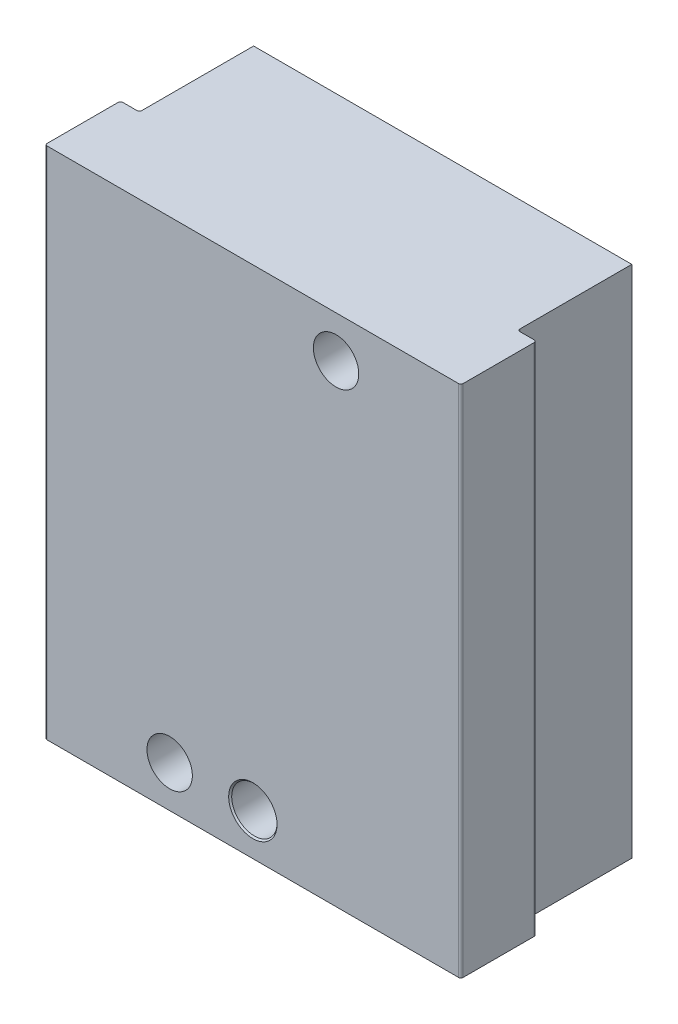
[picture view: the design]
ISO-10303-21;
HEADER;
FILE_DESCRIPTION(('STEP AP214'),'2;1');
FILE_NAME('part.step','',(''),(''),'','','');
FILE_SCHEMA(('AUTOMOTIVE_DESIGN { 1 0 10303 214 1 1 1 1 }'));
ENDSEC;
DATA;
#1=APPLICATION_CONTEXT('core data for automotive mechanical design processes');
#2=APPLICATION_PROTOCOL_DEFINITION('international standard','automotive_design',2000,#1);
#3=PRODUCT_CONTEXT('',#1,'mechanical');
#4=PRODUCT('Part','Part','',(#3));
#5=PRODUCT_RELATED_PRODUCT_CATEGORY('part','',(#4));
#6=PRODUCT_DEFINITION_FORMATION('','',#4);
#7=PRODUCT_DEFINITION_CONTEXT('part definition',#1,'design');
#8=PRODUCT_DEFINITION('design','',#6,#7);
#9=PRODUCT_DEFINITION_SHAPE('','',#8);
#10=(LENGTH_UNIT() NAMED_UNIT(*) SI_UNIT(.MILLI.,.METRE.));
#11=(NAMED_UNIT(*) PLANE_ANGLE_UNIT() SI_UNIT($,.RADIAN.));
#12=(NAMED_UNIT(*) SI_UNIT($,.STERADIAN.) SOLID_ANGLE_UNIT());
#13=UNCERTAINTY_MEASURE_WITH_UNIT(LENGTH_MEASURE(1.E-05),#10,'distance_accuracy_value','');
#14=(GEOMETRIC_REPRESENTATION_CONTEXT(3) GLOBAL_UNCERTAINTY_ASSIGNED_CONTEXT((#13)) GLOBAL_UNIT_ASSIGNED_CONTEXT((#10,
#11,#12)) REPRESENTATION_CONTEXT('',''));
#15=CARTESIAN_POINT('',(0.,0.,0.));
#16=DIRECTION('',(0.,0.,1.));
#17=DIRECTION('',(1.,0.,0.));
#18=AXIS2_PLACEMENT_3D('',#15,#16,#17);
#19=CARTESIAN_POINT('',(0.,5.5,0.));
#20=DIRECTION('',(0.,0.,-1.));
#21=DIRECTION('',(-1.,0.,0.));
#22=AXIS2_PLACEMENT_3D('',#19,#20,#21);
#23=CYLINDRICAL_SURFACE('',#22,1.5);
#24=CARTESIAN_POINT('',(0.,5.5,-25.1));
#25=DIRECTION('',(0.,0.,-1.));
#26=DIRECTION('',(-1.,0.,0.));
#27=AXIS2_PLACEMENT_3D('',#24,#25,#26);
#28=CIRCLE('',#27,1.5);
#29=CARTESIAN_POINT('',(-1.5,5.5,-25.1));
#30=VERTEX_POINT('',#29);
#31=EDGE_CURVE('E572',#30,#30,#28,.T.);
#32=ORIENTED_EDGE('',*,*,#31,.T.);
#33=EDGE_LOOP('',(#32));
#34=FACE_BOUND('',#33,.T.);
#35=CARTESIAN_POINT('',(0.,5.5,-10.));
#36=DIRECTION('',(0.,0.,1.));
#37=DIRECTION('',(1.,0.,0.));
#38=AXIS2_PLACEMENT_3D('',#35,#36,#37);
#39=CIRCLE('',#38,1.5);
#40=CARTESIAN_POINT('',(1.5,5.5,-10.));
#41=VERTEX_POINT('',#40);
#42=EDGE_CURVE('E571',#41,#41,#39,.F.);
#43=ORIENTED_EDGE('',*,*,#42,.F.);
#44=EDGE_LOOP('',(#43));
#45=FACE_BOUND('',#44,.T.);
#46=ADVANCED_FACE('F33',(#34,#45),#23,.F.);
#47=CARTESIAN_POINT('',(27.5,68.,-10.));
#48=DIRECTION('',(-1.,0.,0.));
#49=DIRECTION('',(0.,0.,1.));
#50=AXIS2_PLACEMENT_3D('',#47,#48,#49);
#51=PLANE('',#50);
#52=DIRECTION('',(0.,0.,-1.));
#53=VECTOR('',#52,1.);
#54=CARTESIAN_POINT('',(27.5,0.,-10.));
#55=LINE('',#54,#53);
#56=CARTESIAN_POINT('',(27.5,0.,-0.3));
#57=VERTEX_POINT('',#56);
#58=CARTESIAN_POINT('',(27.5,0.,-9.7));
#59=VERTEX_POINT('',#58);
#60=EDGE_CURVE('E585',#57,#59,#55,.T.);
#61=ORIENTED_EDGE('',*,*,#60,.T.);
#62=DIRECTION('',(0.,-1.,0.));
#63=VECTOR('',#62,1.);
#64=CARTESIAN_POINT('',(27.5,68.,-9.7));
#65=LINE('',#64,#63);
#66=CARTESIAN_POINT('',(27.5,68.,-9.7));
#67=VERTEX_POINT('',#66);
#68=EDGE_CURVE('E653',#59,#67,#65,.F.);
#69=ORIENTED_EDGE('',*,*,#68,.T.);
#70=DIRECTION('',(0.,0.,-1.));
#71=VECTOR('',#70,1.);
#72=CARTESIAN_POINT('',(27.5,68.,-10.));
#73=LINE('',#72,#71);
#74=CARTESIAN_POINT('',(27.5,68.,-0.3));
#75=VERTEX_POINT('',#74);
#76=EDGE_CURVE('E588',#75,#67,#73,.T.);
#77=ORIENTED_EDGE('',*,*,#76,.F.);
#78=DIRECTION('',(0.,-1.,0.));
#79=VECTOR('',#78,1.);
#80=CARTESIAN_POINT('',(27.5,68.,-0.3));
#81=LINE('',#80,#79);
#82=EDGE_CURVE('E650',#75,#57,#81,.T.);
#83=ORIENTED_EDGE('',*,*,#82,.T.);
#84=EDGE_LOOP('',(#61,#69,#77,#83));
#85=FACE_BOUND('',#84,.T.);
#86=ADVANCED_FACE('F893',(#85),#51,.F.);
#87=CARTESIAN_POINT('',(27.5,68.,-10.));
#88=DIRECTION('',(0.,0.,1.));
#89=DIRECTION('',(1.,0.,0.));
#90=AXIS2_PLACEMENT_3D('',#87,#88,#89);
#91=PLANE('',#90);
#92=DIRECTION('',(-1.,0.,0.));
#93=VECTOR('',#92,1.);
#94=CARTESIAN_POINT('',(27.5,68.,-10.));
#95=LINE('',#94,#93);
#96=CARTESIAN_POINT('',(27.2,68.,-10.));
#97=VERTEX_POINT('',#96);
#98=CARTESIAN_POINT('',(25.3,68.,-10.));
#99=VERTEX_POINT('',#98);
#100=EDGE_CURVE('E591',#97,#99,#95,.T.);
#101=ORIENTED_EDGE('',*,*,#100,.F.);
#102=DIRECTION('',(0.,-1.,0.));
#103=VECTOR('',#102,1.);
#104=CARTESIAN_POINT('',(27.2,68.,-10.));
#105=LINE('',#104,#103);
#106=CARTESIAN_POINT('',(27.2,0.,-10.));
#107=VERTEX_POINT('',#106);
#108=EDGE_CURVE('E639',#97,#107,#105,.T.);
#109=ORIENTED_EDGE('',*,*,#108,.T.);
#110=DIRECTION('',(-1.,0.,0.));
#111=VECTOR('',#110,1.);
#112=CARTESIAN_POINT('',(27.5,0.,-10.));
#113=LINE('',#112,#111);
#114=CARTESIAN_POINT('',(25.3,0.,-10.));
#115=VERTEX_POINT('',#114);
#116=EDGE_CURVE('E614',#107,#115,#113,.T.);
#117=ORIENTED_EDGE('',*,*,#116,.T.);
#118=DIRECTION('',(0.,-1.,0.));
#119=VECTOR('',#118,1.);
#120=CARTESIAN_POINT('',(25.3,68.,-10.));
#121=LINE('',#120,#119);
#122=EDGE_CURVE('E637',#115,#99,#121,.F.);
#123=ORIENTED_EDGE('',*,*,#122,.T.);
#124=EDGE_LOOP('',(#101,#109,#117,#123));
#125=FACE_BOUND('',#124,.T.);
#126=ADVANCED_FACE('F899',(#125),#91,.F.);
#127=CARTESIAN_POINT('',(25.,68.,-25.1));
#128=DIRECTION('',(-1.,0.,0.));
#129=DIRECTION('',(0.,0.,1.));
#130=AXIS2_PLACEMENT_3D('',#127,#128,#129);
#131=PLANE('',#130);
#132=DIRECTION('',(0.,0.,-1.));
#133=VECTOR('',#132,1.);
#134=CARTESIAN_POINT('',(25.,68.,-25.1));
#135=LINE('',#134,#133);
#136=CARTESIAN_POINT('',(25.,68.,-10.3));
#137=VERTEX_POINT('',#136);
#138=CARTESIAN_POINT('',(25.,68.,-25.1));
#139=VERTEX_POINT('',#138);
#140=EDGE_CURVE('E595',#137,#139,#135,.T.);
#141=ORIENTED_EDGE('',*,*,#140,.F.);
#142=DIRECTION('',(0.,-1.,0.));
#143=VECTOR('',#142,1.);
#144=CARTESIAN_POINT('',(25.,0.,-10.3));
#145=LINE('',#144,#143);
#146=CARTESIAN_POINT('',(25.,0.,-10.3));
#147=VERTEX_POINT('',#146);
#148=EDGE_CURVE('E663',#137,#147,#145,.T.);
#149=ORIENTED_EDGE('',*,*,#148,.T.);
#150=DIRECTION('',(0.,0.,-1.));
#151=VECTOR('',#150,1.);
#152=CARTESIAN_POINT('',(25.,0.,-25.1));
#153=LINE('',#152,#151);
#154=CARTESIAN_POINT('',(25.,0.,-25.1));
#155=VERTEX_POINT('',#154);
#156=EDGE_CURVE('E617',#147,#155,#153,.T.);
#157=ORIENTED_EDGE('',*,*,#156,.T.);
#158=DIRECTION('',(0.,-1.,0.));
#159=VECTOR('',#158,1.);
#160=CARTESIAN_POINT('',(25.,68.,-25.1));
#161=LINE('',#160,#159);
#162=EDGE_CURVE('E634',#139,#155,#161,.T.);
#163=ORIENTED_EDGE('',*,*,#162,.F.);
#164=EDGE_LOOP('',(#141,#149,#157,#163));
#165=FACE_BOUND('',#164,.T.);
#166=ADVANCED_FACE('F944',(#165),#131,.F.);
#167=CARTESIAN_POINT('',(-25.,68.,-25.1));
#168=DIRECTION('',(0.,0.,1.));
#169=DIRECTION('',(1.,0.,0.));
#170=AXIS2_PLACEMENT_3D('',#167,#168,#169);
#171=PLANE('',#170);
#172=DIRECTION('',(0.,1.,0.));
#173=VECTOR('',#172,1.);
#174=CARTESIAN_POINT('',(-16.125,68.,-25.1));
#175=LINE('',#174,#173);
#176=CARTESIAN_POINT('',(-16.125,14.525,-25.1));
#177=VERTEX_POINT('',#176);
#178=CARTESIAN_POINT('',(-16.125,18.9237901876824,-25.1));
#179=VERTEX_POINT('',#178);
#180=EDGE_CURVE('E41',#177,#179,#175,.T.);
#181=ORIENTED_EDGE('',*,*,#180,.F.);
#182=CARTESIAN_POINT('',(-14.075,14.525,-25.1));
#183=DIRECTION('',(0.,0.,1.));
#184=DIRECTION('',(1.,0.,0.));
#185=AXIS2_PLACEMENT_3D('',#182,#183,#184);
#186=CIRCLE('',#185,2.05);
#187=CARTESIAN_POINT('',(-14.075,12.475,-25.1));
#188=VERTEX_POINT('',#187);
#189=EDGE_CURVE('E11',#177,#188,#186,.T.);
#190=ORIENTED_EDGE('',*,*,#189,.T.);
#191=DIRECTION('',(-1.,0.,0.));
#192=VECTOR('',#191,1.);
#193=CARTESIAN_POINT('',(-25.,12.475,-25.1));
#194=LINE('',#193,#192);
#195=CARTESIAN_POINT('',(-7.92500000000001,12.475,-25.1));
#196=VERTEX_POINT('',#195);
#197=EDGE_CURVE('E787',#196,#188,#194,.T.);
#198=ORIENTED_EDGE('',*,*,#197,.F.);
#199=CARTESIAN_POINT('',(-7.92500000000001,14.525,-25.1));
#200=DIRECTION('',(0.,0.,1.));
#201=DIRECTION('',(1.,0.,0.));
#202=AXIS2_PLACEMENT_3D('',#199,#200,#201);
#203=CIRCLE('',#202,2.05);
#204=CARTESIAN_POINT('',(-5.87500000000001,14.525,-25.1));
#205=VERTEX_POINT('',#204);
#206=EDGE_CURVE('E781',#196,#205,#203,.T.);
#207=ORIENTED_EDGE('',*,*,#206,.T.);
#208=DIRECTION('',(0.,-1.,0.));
#209=VECTOR('',#208,1.);
#210=CARTESIAN_POINT('',(-5.87499999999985,67.9999999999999,-25.1));
#211=LINE('',#210,#209);
#212=CARTESIAN_POINT('',(-5.87499999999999,18.9237901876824,-25.1));
#213=VERTEX_POINT('',#212);
#214=EDGE_CURVE('E779',#213,#205,#211,.T.);
#215=ORIENTED_EDGE('',*,*,#214,.F.);
#216=CARTESIAN_POINT('',(-7.92499999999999,18.9237901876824,-25.1));
#217=DIRECTION('',(0.,0.,1.));
#218=DIRECTION('',(1.,0.,0.));
#219=AXIS2_PLACEMENT_3D('',#216,#217,#218);
#220=CIRCLE('',#219,2.05);
#221=CARTESIAN_POINT('',(-6.285,20.1537901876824,-25.1));
#222=VERTEX_POINT('',#221);
#223=EDGE_CURVE('E774',#213,#222,#220,.T.);
#224=ORIENTED_EDGE('',*,*,#223,.T.);
#225=CARTESIAN_POINT('',(0.274999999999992,25.0737901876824,-25.1));
#226=DIRECTION('',(0.,0.,1.));
#227=DIRECTION('',(1.,0.,0.));
#228=AXIS2_PLACEMENT_3D('',#225,#226,#227);
#229=CIRCLE('',#228,8.2);
#230=CARTESIAN_POINT('',(-7.92500000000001,25.0737901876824,-25.1));
#231=VERTEX_POINT('',#230);
#232=EDGE_CURVE('E769',#231,#222,#229,.T.);
#233=ORIENTED_EDGE('',*,*,#232,.F.);
#234=DIRECTION('',(0.,-1.,0.));
#235=VECTOR('',#234,1.);
#236=CARTESIAN_POINT('',(-7.92500000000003,68.,-25.1));
#237=LINE('',#236,#235);
#238=CARTESIAN_POINT('',(-7.92500000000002,42.9262098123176,-25.1));
#239=VERTEX_POINT('',#238);
#240=EDGE_CURVE('E764',#239,#231,#237,.T.);
#241=ORIENTED_EDGE('',*,*,#240,.F.);
#242=CARTESIAN_POINT('',(0.274999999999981,42.9262098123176,-25.1));
#243=DIRECTION('',(0.,0.,1.));
#244=DIRECTION('',(1.,0.,0.));
#245=AXIS2_PLACEMENT_3D('',#242,#243,#244);
#246=CIRCLE('',#245,8.2);
#247=CARTESIAN_POINT('',(-6.28500000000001,47.8462098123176,-25.1));
#248=VERTEX_POINT('',#247);
#249=EDGE_CURVE('E760',#248,#239,#246,.T.);
#250=ORIENTED_EDGE('',*,*,#249,.F.);
#251=CARTESIAN_POINT('',(-7.92500000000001,49.0762098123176,-25.1));
#252=DIRECTION('',(0.,0.,1.));
#253=DIRECTION('',(1.,0.,0.));
#254=AXIS2_PLACEMENT_3D('',#251,#252,#253);
#255=CIRCLE('',#254,2.05);
#256=CARTESIAN_POINT('',(-5.87500000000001,49.0762098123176,-25.1));
#257=VERTEX_POINT('',#256);
#258=EDGE_CURVE('E754',#248,#257,#255,.T.);
#259=ORIENTED_EDGE('',*,*,#258,.T.);
#260=DIRECTION('',(0.,-1.,0.));
#261=VECTOR('',#260,1.);
#262=CARTESIAN_POINT('',(-5.87500000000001,68.,-25.1));
#263=LINE('',#262,#261);
#264=CARTESIAN_POINT('',(-5.87500000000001,53.475,-25.1));
#265=VERTEX_POINT('',#264);
#266=EDGE_CURVE('E752',#265,#257,#263,.T.);
#267=ORIENTED_EDGE('',*,*,#266,.F.);
#268=CARTESIAN_POINT('',(-7.92500000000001,53.475,-25.1));
#269=DIRECTION('',(0.,0.,1.));
#270=DIRECTION('',(1.,0.,0.));
#271=AXIS2_PLACEMENT_3D('',#268,#269,#270);
#272=CIRCLE('',#271,2.05);
#273=CARTESIAN_POINT('',(-7.92500000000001,55.525,-25.1));
#274=VERTEX_POINT('',#273);
#275=EDGE_CURVE('E747',#265,#274,#272,.T.);
#276=ORIENTED_EDGE('',*,*,#275,.T.);
#277=DIRECTION('',(1.,0.,0.));
#278=VECTOR('',#277,1.);
#279=CARTESIAN_POINT('',(-25.,55.525,-25.1));
#280=LINE('',#279,#278);
#281=CARTESIAN_POINT('',(-14.075,55.525,-25.1));
#282=VERTEX_POINT('',#281);
#283=EDGE_CURVE('E750',#282,#274,#280,.T.);
#284=ORIENTED_EDGE('',*,*,#283,.F.);
#285=CARTESIAN_POINT('',(-14.075,53.475,-25.1));
#286=DIRECTION('',(0.,0.,1.));
#287=DIRECTION('',(1.,0.,0.));
#288=AXIS2_PLACEMENT_3D('',#285,#286,#287);
#289=CIRCLE('',#288,2.05);
#290=CARTESIAN_POINT('',(-16.125,53.475,-25.1));
#291=VERTEX_POINT('',#290);
#292=EDGE_CURVE('E757',#282,#291,#289,.T.);
#293=ORIENTED_EDGE('',*,*,#292,.T.);
#294=DIRECTION('',(0.,1.,0.));
#295=VECTOR('',#294,1.);
#296=CARTESIAN_POINT('',(-16.125,68.,-25.1));
#297=LINE('',#296,#295);
#298=CARTESIAN_POINT('',(-16.125,49.0762098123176,-25.1));
#299=VERTEX_POINT('',#298);
#300=EDGE_CURVE('E762',#299,#291,#297,.T.);
#301=ORIENTED_EDGE('',*,*,#300,.F.);
#302=CARTESIAN_POINT('',(-14.075,49.0762098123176,-25.1));
#303=DIRECTION('',(0.,0.,1.));
#304=DIRECTION('',(1.,0.,0.));
#305=AXIS2_PLACEMENT_3D('',#302,#303,#304);
#306=CIRCLE('',#305,2.05);
#307=CARTESIAN_POINT('',(-15.715,47.8462098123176,-25.1));
#308=VERTEX_POINT('',#307);
#309=EDGE_CURVE('E766',#299,#308,#306,.T.);
#310=ORIENTED_EDGE('',*,*,#309,.T.);
#311=CARTESIAN_POINT('',(-22.275,42.9262098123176,-25.1));
#312=DIRECTION('',(0.,0.,1.));
#313=DIRECTION('',(1.,0.,0.));
#314=AXIS2_PLACEMENT_3D('',#311,#312,#313);
#315=CIRCLE('',#314,8.2);
#316=CARTESIAN_POINT('',(-14.075,42.9262098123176,-25.1));
#317=VERTEX_POINT('',#316);
#318=EDGE_CURVE('E771',#317,#308,#315,.T.);
#319=ORIENTED_EDGE('',*,*,#318,.F.);
#320=DIRECTION('',(0.,1.,0.));
#321=VECTOR('',#320,1.);
#322=CARTESIAN_POINT('',(-14.075,68.,-25.1));
#323=LINE('',#322,#321);
#324=CARTESIAN_POINT('',(-14.075,25.0737901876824,-25.1));
#325=VERTEX_POINT('',#324);
#326=EDGE_CURVE('E402',#325,#317,#323,.T.);
#327=ORIENTED_EDGE('',*,*,#326,.F.);
#328=CARTESIAN_POINT('',(-22.275,25.0737901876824,-25.1));
#329=DIRECTION('',(0.,0.,1.));
#330=DIRECTION('',(1.,0.,0.));
#331=AXIS2_PLACEMENT_3D('',#328,#329,#330);
#332=CIRCLE('',#331,8.2);
#333=CARTESIAN_POINT('',(-15.715,20.1537901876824,-25.1));
#334=VERTEX_POINT('',#333);
#335=EDGE_CURVE('E777',#334,#325,#332,.T.);
#336=ORIENTED_EDGE('',*,*,#335,.F.);
#337=CARTESIAN_POINT('',(-14.075,18.9237901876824,-25.1));
#338=DIRECTION('',(0.,0.,1.));
#339=DIRECTION('',(1.,0.,0.));
#340=AXIS2_PLACEMENT_3D('',#337,#338,#339);
#341=CIRCLE('',#340,2.05);
#342=EDGE_CURVE('E784',#334,#179,#341,.T.);
#343=ORIENTED_EDGE('',*,*,#342,.T.);
#344=EDGE_LOOP('',(#181,#190,#198,#207,#215,#224,#233,#241,#250,#259,#267,#276,#284,#293,#301,
#310,#319,#327,#336,#343));
#345=FACE_BOUND('',#344,.T.);
#346=DIRECTION('',(-1.,0.,0.));
#347=VECTOR('',#346,1.);
#348=CARTESIAN_POINT('',(-25.,12.475,-25.1));
#349=LINE('',#348,#347);
#350=CARTESIAN_POINT('',(14.075,12.475,-25.1));
#351=VERTEX_POINT('',#350);
#352=CARTESIAN_POINT('',(7.92499999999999,12.475,-25.1));
#353=VERTEX_POINT('',#352);
#354=EDGE_CURVE('E740',#351,#353,#349,.T.);
#355=ORIENTED_EDGE('',*,*,#354,.F.);
#356=CARTESIAN_POINT('',(14.075,14.525,-25.1));
#357=DIRECTION('',(0.,0.,1.));
#358=DIRECTION('',(1.,0.,0.));
#359=AXIS2_PLACEMENT_3D('',#356,#357,#358);
#360=CIRCLE('',#359,2.05);
#361=CARTESIAN_POINT('',(16.125,14.525,-25.1));
#362=VERTEX_POINT('',#361);
#363=EDGE_CURVE('E744',#351,#362,#360,.T.);
#364=ORIENTED_EDGE('',*,*,#363,.T.);
#365=DIRECTION('',(0.,-1.,0.));
#366=VECTOR('',#365,1.);
#367=CARTESIAN_POINT('',(16.125,68.,-25.1));
#368=LINE('',#367,#366);
#369=CARTESIAN_POINT('',(16.125,18.9237901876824,-25.1));
#370=VERTEX_POINT('',#369);
#371=EDGE_CURVE('E742',#370,#362,#368,.T.);
#372=ORIENTED_EDGE('',*,*,#371,.F.);
#373=CARTESIAN_POINT('',(14.075,18.9237901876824,-25.1));
#374=DIRECTION('',(0.,0.,1.));
#375=DIRECTION('',(1.,0.,0.));
#376=AXIS2_PLACEMENT_3D('',#373,#374,#375);
#377=CIRCLE('',#376,2.05);
#378=CARTESIAN_POINT('',(15.715,20.1537901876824,-25.1));
#379=VERTEX_POINT('',#378);
#380=EDGE_CURVE('E737',#370,#379,#377,.T.);
#381=ORIENTED_EDGE('',*,*,#380,.T.);
#382=CARTESIAN_POINT('',(22.275,25.0737901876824,-25.1));
#383=DIRECTION('',(0.,0.,1.));
#384=DIRECTION('',(1.,0.,0.));
#385=AXIS2_PLACEMENT_3D('',#382,#383,#384);
#386=CIRCLE('',#385,8.2);
#387=CARTESIAN_POINT('',(14.075,25.0737901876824,-25.1));
#388=VERTEX_POINT('',#387);
#389=EDGE_CURVE('E730',#388,#379,#386,.T.);
#390=ORIENTED_EDGE('',*,*,#389,.F.);
#391=DIRECTION('',(0.,-1.,0.));
#392=VECTOR('',#391,1.);
#393=CARTESIAN_POINT('',(14.075,68.,-25.1));
#394=LINE('',#393,#392);
#395=CARTESIAN_POINT('',(14.075,42.9262098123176,-25.1));
#396=VERTEX_POINT('',#395);
#397=EDGE_CURVE('E725',#396,#388,#394,.T.);
#398=ORIENTED_EDGE('',*,*,#397,.F.);
#399=CARTESIAN_POINT('',(22.275,42.9262098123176,-25.1));
#400=DIRECTION('',(0.,0.,1.));
#401=DIRECTION('',(1.,0.,0.));
#402=AXIS2_PLACEMENT_3D('',#399,#400,#401);
#403=CIRCLE('',#402,8.2);
#404=CARTESIAN_POINT('',(15.715,47.8462098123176,-25.1));
#405=VERTEX_POINT('',#404);
#406=EDGE_CURVE('E723',#405,#396,#403,.T.);
#407=ORIENTED_EDGE('',*,*,#406,.F.);
#408=CARTESIAN_POINT('',(14.075,49.0762098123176,-25.1));
#409=DIRECTION('',(0.,0.,1.));
#410=DIRECTION('',(1.,0.,0.));
#411=AXIS2_PLACEMENT_3D('',#408,#409,#410);
#412=CIRCLE('',#411,2.05);
#413=CARTESIAN_POINT('',(16.125,49.0762098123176,-25.1));
#414=VERTEX_POINT('',#413);
#415=EDGE_CURVE('E718',#405,#414,#412,.T.);
#416=ORIENTED_EDGE('',*,*,#415,.T.);
#417=DIRECTION('',(0.,-1.,0.));
#418=VECTOR('',#417,1.);
#419=CARTESIAN_POINT('',(16.125,68.,-25.1));
#420=LINE('',#419,#418);
#421=CARTESIAN_POINT('',(16.125,53.475,-25.1));
#422=VERTEX_POINT('',#421);
#423=EDGE_CURVE('E714',#422,#414,#420,.T.);
#424=ORIENTED_EDGE('',*,*,#423,.F.);
#425=CARTESIAN_POINT('',(14.075,53.475,-25.1));
#426=DIRECTION('',(0.,0.,1.));
#427=DIRECTION('',(1.,0.,0.));
#428=AXIS2_PLACEMENT_3D('',#425,#426,#427);
#429=CIRCLE('',#428,2.05);
#430=CARTESIAN_POINT('',(14.075,55.525,-25.1));
#431=VERTEX_POINT('',#430);
#432=EDGE_CURVE('E709',#422,#431,#429,.T.);
#433=ORIENTED_EDGE('',*,*,#432,.T.);
#434=DIRECTION('',(1.,0.,0.));
#435=VECTOR('',#434,1.);
#436=CARTESIAN_POINT('',(-25.,55.525,-25.1));
#437=LINE('',#436,#435);
#438=CARTESIAN_POINT('',(7.92500000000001,55.525,-25.1));
#439=VERTEX_POINT('',#438);
#440=EDGE_CURVE('E702',#439,#431,#437,.T.);
#441=ORIENTED_EDGE('',*,*,#440,.F.);
#442=CARTESIAN_POINT('',(7.92500000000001,53.475,-25.1));
#443=DIRECTION('',(0.,0.,1.));
#444=DIRECTION('',(1.,0.,0.));
#445=AXIS2_PLACEMENT_3D('',#442,#443,#444);
#446=CIRCLE('',#445,2.05);
#447=CARTESIAN_POINT('',(5.87500000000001,53.475,-25.1));
#448=VERTEX_POINT('',#447);
#449=EDGE_CURVE('E699',#439,#448,#446,.T.);
#450=ORIENTED_EDGE('',*,*,#449,.T.);
#451=DIRECTION('',(0.,1.,0.));
#452=VECTOR('',#451,1.);
#453=CARTESIAN_POINT('',(5.87500000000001,68.,-25.1));
#454=LINE('',#453,#452);
#455=CARTESIAN_POINT('',(5.875,49.0762098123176,-25.1));
#456=VERTEX_POINT('',#455);
#457=EDGE_CURVE('E704',#456,#448,#454,.T.);
#458=ORIENTED_EDGE('',*,*,#457,.F.);
#459=CARTESIAN_POINT('',(7.92500000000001,49.0762098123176,-25.1));
#460=DIRECTION('',(0.,0.,1.));
#461=DIRECTION('',(1.,0.,0.));
#462=AXIS2_PLACEMENT_3D('',#459,#460,#461);
#463=CIRCLE('',#462,2.05);
#464=CARTESIAN_POINT('',(6.28500000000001,47.8462098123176,-25.1));
#465=VERTEX_POINT('',#464);
#466=EDGE_CURVE('E706',#456,#465,#463,.T.);
#467=ORIENTED_EDGE('',*,*,#466,.T.);
#468=CARTESIAN_POINT('',(-0.27499999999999,42.9262098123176,-25.1));
#469=DIRECTION('',(0.,0.,1.));
#470=DIRECTION('',(1.,0.,0.));
#471=AXIS2_PLACEMENT_3D('',#468,#469,#470);
#472=CIRCLE('',#471,8.2);
#473=CARTESIAN_POINT('',(7.92500000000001,42.9262098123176,-25.1));
#474=VERTEX_POINT('',#473);
#475=EDGE_CURVE('E712',#474,#465,#472,.T.);
#476=ORIENTED_EDGE('',*,*,#475,.F.);
#477=DIRECTION('',(0.,1.,0.));
#478=VECTOR('',#477,1.);
#479=CARTESIAN_POINT('',(7.92500000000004,68.,-25.1));
#480=LINE('',#479,#478);
#481=CARTESIAN_POINT('',(7.925,25.0737901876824,-25.1));
#482=VERTEX_POINT('',#481);
#483=EDGE_CURVE('E716',#482,#474,#480,.T.);
#484=ORIENTED_EDGE('',*,*,#483,.F.);
#485=CARTESIAN_POINT('',(-0.275000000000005,25.0737901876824,-25.1));
#486=DIRECTION('',(0.,0.,1.));
#487=DIRECTION('',(1.,0.,0.));
#488=AXIS2_PLACEMENT_3D('',#485,#486,#487);
#489=CIRCLE('',#488,8.2);
#490=CARTESIAN_POINT('',(6.28499999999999,20.1537901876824,-25.1));
#491=VERTEX_POINT('',#490);
#492=EDGE_CURVE('E721',#491,#482,#489,.T.);
#493=ORIENTED_EDGE('',*,*,#492,.F.);
#494=CARTESIAN_POINT('',(7.92499999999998,18.9237901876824,-25.1));
#495=DIRECTION('',(0.,0.,1.));
#496=DIRECTION('',(1.,0.,0.));
#497=AXIS2_PLACEMENT_3D('',#494,#495,#496);
#498=CIRCLE('',#497,2.05);
#499=CARTESIAN_POINT('',(5.87499999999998,18.9237901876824,-25.1));
#500=VERTEX_POINT('',#499);
#501=EDGE_CURVE('E727',#491,#500,#498,.T.);
#502=ORIENTED_EDGE('',*,*,#501,.T.);
#503=DIRECTION('',(0.,1.,0.));
#504=VECTOR('',#503,1.);
#505=CARTESIAN_POINT('',(5.87499999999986,68.0000000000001,-25.1));
#506=LINE('',#505,#504);
#507=CARTESIAN_POINT('',(5.87499999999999,14.525,-25.1));
#508=VERTEX_POINT('',#507);
#509=EDGE_CURVE('E732',#508,#500,#506,.T.);
#510=ORIENTED_EDGE('',*,*,#509,.F.);
#511=CARTESIAN_POINT('',(7.92499999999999,14.525,-25.1));
#512=DIRECTION('',(0.,0.,1.));
#513=DIRECTION('',(1.,0.,0.));
#514=AXIS2_PLACEMENT_3D('',#511,#512,#513);
#515=CIRCLE('',#514,2.05);
#516=EDGE_CURVE('E734',#508,#353,#515,.T.);
#517=ORIENTED_EDGE('',*,*,#516,.T.);
#518=EDGE_LOOP('',(#355,#364,#372,#381,#390,#398,#407,#416,#424,#433,#441,#450,#458,#467,#476,
#484,#493,#502,#510,#517));
#519=FACE_BOUND('',#518,.T.);
#520=ORIENTED_EDGE('',*,*,#31,.F.);
#521=EDGE_LOOP('',(#520));
#522=FACE_BOUND('',#521,.T.);
#523=CARTESIAN_POINT('',(-11.,5.5,-25.1));
#524=DIRECTION('',(0.,0.,-1.));
#525=DIRECTION('',(-1.,0.,0.));
#526=AXIS2_PLACEMENT_3D('',#523,#524,#525);
#527=CIRCLE('',#526,3.);
#528=CARTESIAN_POINT('',(-14.,5.5,-25.1));
#529=VERTEX_POINT('',#528);
#530=EDGE_CURVE('E575',#529,#529,#527,.T.);
#531=ORIENTED_EDGE('',*,*,#530,.F.);
#532=EDGE_LOOP('',(#531));
#533=FACE_BOUND('',#532,.T.);
#534=CARTESIAN_POINT('',(11.,62.5,-25.1));
#535=DIRECTION('',(0.,0.,-1.));
#536=DIRECTION('',(-1.,0.,0.));
#537=AXIS2_PLACEMENT_3D('',#534,#535,#536);
#538=CIRCLE('',#537,3.);
#539=CARTESIAN_POINT('',(8.,62.5,-25.1));
#540=VERTEX_POINT('',#539);
#541=EDGE_CURVE('E579',#540,#540,#538,.T.);
#542=ORIENTED_EDGE('',*,*,#541,.F.);
#543=EDGE_LOOP('',(#542));
#544=FACE_BOUND('',#543,.T.);
#545=DIRECTION('',(-1.,0.,0.));
#546=VECTOR('',#545,1.);
#547=CARTESIAN_POINT('',(-25.,0.,-25.1));
#548=LINE('',#547,#546);
#549=CARTESIAN_POINT('',(-25.,0.,-25.1));
#550=VERTEX_POINT('',#549);
#551=EDGE_CURVE('E619',#155,#550,#548,.T.);
#552=ORIENTED_EDGE('',*,*,#551,.T.);
#553=DIRECTION('',(0.,-1.,0.));
#554=VECTOR('',#553,1.);
#555=CARTESIAN_POINT('',(-25.,68.,-25.1));
#556=LINE('',#555,#554);
#557=CARTESIAN_POINT('',(-25.,68.,-25.1));
#558=VERTEX_POINT('',#557);
#559=EDGE_CURVE('E611',#558,#550,#556,.T.);
#560=ORIENTED_EDGE('',*,*,#559,.F.);
#561=DIRECTION('',(-1.,0.,0.));
#562=VECTOR('',#561,1.);
#563=CARTESIAN_POINT('',(-25.,68.,-25.1));
#564=LINE('',#563,#562);
#565=EDGE_CURVE('E597',#139,#558,#564,.T.);
#566=ORIENTED_EDGE('',*,*,#565,.F.);
#567=ORIENTED_EDGE('',*,*,#162,.T.);
#568=EDGE_LOOP('',(#552,#560,#566,#567));
#569=FACE_BOUND('',#568,.T.);
#570=ADVANCED_FACE('F800',(#345,#519,#522,#533,#544,#569),#171,.F.);
#571=CARTESIAN_POINT('',(-25.,68.,-25.1));
#572=DIRECTION('',(1.,0.,0.));
#573=DIRECTION('',(0.,0.,-1.));
#574=AXIS2_PLACEMENT_3D('',#571,#572,#573);
#575=PLANE('',#574);
#576=DIRECTION('',(0.,0.,1.));
#577=VECTOR('',#576,1.);
#578=CARTESIAN_POINT('',(-25.,0.,-25.1));
#579=LINE('',#578,#577);
#580=CARTESIAN_POINT('',(-25.,0.,-10.3));
#581=VERTEX_POINT('',#580);
#582=EDGE_CURVE('E621',#550,#581,#579,.T.);
#583=ORIENTED_EDGE('',*,*,#582,.T.);
#584=DIRECTION('',(0.,-1.,0.));
#585=VECTOR('',#584,1.);
#586=CARTESIAN_POINT('',(-25.,68.,-10.3));
#587=LINE('',#586,#585);
#588=CARTESIAN_POINT('',(-25.,68.,-10.3));
#589=VERTEX_POINT('',#588);
#590=EDGE_CURVE('E671',#581,#589,#587,.F.);
#591=ORIENTED_EDGE('',*,*,#590,.T.);
#592=DIRECTION('',(0.,0.,1.));
#593=VECTOR('',#592,1.);
#594=CARTESIAN_POINT('',(-25.,68.,-25.1));
#595=LINE('',#594,#593);
#596=EDGE_CURVE('E599',#558,#589,#595,.T.);
#597=ORIENTED_EDGE('',*,*,#596,.F.);
#598=ORIENTED_EDGE('',*,*,#559,.T.);
#599=EDGE_LOOP('',(#583,#591,#597,#598));
#600=FACE_BOUND('',#599,.T.);
#601=ADVANCED_FACE('F937',(#600),#575,.F.);
#602=CARTESIAN_POINT('',(-27.5,68.,-10.));
#603=DIRECTION('',(0.,0.,1.));
#604=DIRECTION('',(1.,0.,0.));
#605=AXIS2_PLACEMENT_3D('',#602,#603,#604);
#606=PLANE('',#605);
#607=DIRECTION('',(-1.,0.,0.));
#608=VECTOR('',#607,1.);
#609=CARTESIAN_POINT('',(-27.5,68.,-10.));
#610=LINE('',#609,#608);
#611=CARTESIAN_POINT('',(-25.3,68.,-10.));
#612=VERTEX_POINT('',#611);
#613=CARTESIAN_POINT('',(-27.2,68.,-10.));
#614=VERTEX_POINT('',#613);
#615=EDGE_CURVE('E602',#612,#614,#610,.T.);
#616=ORIENTED_EDGE('',*,*,#615,.F.);
#617=DIRECTION('',(0.,-1.,0.));
#618=VECTOR('',#617,1.);
#619=CARTESIAN_POINT('',(-25.3,0.,-10.));
#620=LINE('',#619,#618);
#621=CARTESIAN_POINT('',(-25.3,0.,-10.));
#622=VERTEX_POINT('',#621);
#623=EDGE_CURVE('E668',#612,#622,#620,.T.);
#624=ORIENTED_EDGE('',*,*,#623,.T.);
#625=DIRECTION('',(-1.,0.,0.));
#626=VECTOR('',#625,1.);
#627=CARTESIAN_POINT('',(-27.5,0.,-10.));
#628=LINE('',#627,#626);
#629=CARTESIAN_POINT('',(-27.2,0.,-10.));
#630=VERTEX_POINT('',#629);
#631=EDGE_CURVE('E624',#622,#630,#628,.T.);
#632=ORIENTED_EDGE('',*,*,#631,.T.);
#633=DIRECTION('',(0.,-1.,0.));
#634=VECTOR('',#633,1.);
#635=CARTESIAN_POINT('',(-27.2,68.,-10.));
#636=LINE('',#635,#634);
#637=EDGE_CURVE('E666',#630,#614,#636,.F.);
#638=ORIENTED_EDGE('',*,*,#637,.T.);
#639=EDGE_LOOP('',(#616,#624,#632,#638));
#640=FACE_BOUND('',#639,.T.);
#641=ADVANCED_FACE('F933',(#640),#606,.F.);
#642=CARTESIAN_POINT('',(-27.5,68.,-10.));
#643=DIRECTION('',(1.,0.,0.));
#644=DIRECTION('',(0.,0.,-1.));
#645=AXIS2_PLACEMENT_3D('',#642,#643,#644);
#646=PLANE('',#645);
#647=DIRECTION('',(0.,0.,1.));
#648=VECTOR('',#647,1.);
#649=CARTESIAN_POINT('',(-27.5,68.,-10.));
#650=LINE('',#649,#648);
#651=CARTESIAN_POINT('',(-27.5,68.,-9.7));
#652=VERTEX_POINT('',#651);
#653=CARTESIAN_POINT('',(-27.5,68.,-0.3));
#654=VERTEX_POINT('',#653);
#655=EDGE_CURVE('E605',#652,#654,#650,.T.);
#656=ORIENTED_EDGE('',*,*,#655,.F.);
#657=DIRECTION('',(0.,-1.,0.));
#658=VECTOR('',#657,1.);
#659=CARTESIAN_POINT('',(-27.5,68.,-9.7));
#660=LINE('',#659,#658);
#661=CARTESIAN_POINT('',(-27.5,0.,-9.7));
#662=VERTEX_POINT('',#661);
#663=EDGE_CURVE('E675',#652,#662,#660,.T.);
#664=ORIENTED_EDGE('',*,*,#663,.T.);
#665=DIRECTION('',(0.,0.,1.));
#666=VECTOR('',#665,1.);
#667=CARTESIAN_POINT('',(-27.5,0.,-10.));
#668=LINE('',#667,#666);
#669=CARTESIAN_POINT('',(-27.5,0.,-0.3));
#670=VERTEX_POINT('',#669);
#671=EDGE_CURVE('E627',#662,#670,#668,.T.);
#672=ORIENTED_EDGE('',*,*,#671,.T.);
#673=DIRECTION('',(0.,-1.,0.));
#674=VECTOR('',#673,1.);
#675=CARTESIAN_POINT('',(-27.5,68.,-0.3));
#676=LINE('',#675,#674);
#677=EDGE_CURVE('E673',#670,#654,#676,.F.);
#678=ORIENTED_EDGE('',*,*,#677,.T.);
#679=EDGE_LOOP('',(#656,#664,#672,#678));
#680=FACE_BOUND('',#679,.T.);
#681=ADVANCED_FACE('F929',(#680),#646,.F.);
#682=CARTESIAN_POINT('',(-27.5,68.,0.));
#683=DIRECTION('',(0.,0.,-1.));
#684=DIRECTION('',(-1.,0.,0.));
#685=AXIS2_PLACEMENT_3D('',#682,#683,#684);
#686=PLANE('',#685);
#687=CARTESIAN_POINT('',(0.,5.5,0.));
#688=DIRECTION('',(0.,0.,-1.));
#689=DIRECTION('',(-1.,0.,0.));
#690=AXIS2_PLACEMENT_3D('',#687,#688,#689);
#691=CIRCLE('',#690,3.19999999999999);
#692=CARTESIAN_POINT('',(-3.19999999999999,5.5,0.));
#693=VERTEX_POINT('',#692);
#694=EDGE_CURVE('E696',#693,#693,#691,.T.);
#695=ORIENTED_EDGE('',*,*,#694,.T.);
#696=EDGE_LOOP('',(#695));
#697=FACE_BOUND('',#696,.T.);
#698=CARTESIAN_POINT('',(-11.,5.5,0.));
#699=DIRECTION('',(0.,0.,-1.));
#700=DIRECTION('',(-1.,0.,0.));
#701=AXIS2_PLACEMENT_3D('',#698,#699,#700);
#702=CIRCLE('',#701,3.);
#703=CARTESIAN_POINT('',(-14.,5.5,0.));
#704=VERTEX_POINT('',#703);
#705=EDGE_CURVE('E576',#704,#704,#702,.T.);
#706=ORIENTED_EDGE('',*,*,#705,.T.);
#707=EDGE_LOOP('',(#706));
#708=FACE_BOUND('',#707,.T.);
#709=CARTESIAN_POINT('',(11.,62.5,0.));
#710=DIRECTION('',(0.,0.,-1.));
#711=DIRECTION('',(-1.,0.,0.));
#712=AXIS2_PLACEMENT_3D('',#709,#710,#711);
#713=CIRCLE('',#712,3.);
#714=CARTESIAN_POINT('',(8.,62.5,0.));
#715=VERTEX_POINT('',#714);
#716=EDGE_CURVE('E582',#715,#715,#713,.T.);
#717=ORIENTED_EDGE('',*,*,#716,.T.);
#718=EDGE_LOOP('',(#717));
#719=FACE_BOUND('',#718,.T.);
#720=DIRECTION('',(1.,0.,0.));
#721=VECTOR('',#720,1.);
#722=CARTESIAN_POINT('',(-27.5,0.,0.));
#723=LINE('',#722,#721);
#724=CARTESIAN_POINT('',(-27.2,0.,0.));
#725=VERTEX_POINT('',#724);
#726=CARTESIAN_POINT('',(27.2,0.,0.));
#727=VERTEX_POINT('',#726);
#728=EDGE_CURVE('E592',#725,#727,#723,.T.);
#729=ORIENTED_EDGE('',*,*,#728,.T.);
#730=DIRECTION('',(0.,-1.,0.));
#731=VECTOR('',#730,1.);
#732=CARTESIAN_POINT('',(27.2,68.,0.));
#733=LINE('',#732,#731);
#734=CARTESIAN_POINT('',(27.2,68.,0.));
#735=VERTEX_POINT('',#734);
#736=EDGE_CURVE('E681',#727,#735,#733,.F.);
#737=ORIENTED_EDGE('',*,*,#736,.T.);
#738=DIRECTION('',(1.,0.,0.));
#739=VECTOR('',#738,1.);
#740=CARTESIAN_POINT('',(-27.5,68.,0.));
#741=LINE('',#740,#739);
#742=CARTESIAN_POINT('',(-27.2,68.,0.));
#743=VERTEX_POINT('',#742);
#744=EDGE_CURVE('E608',#743,#735,#741,.T.);
#745=ORIENTED_EDGE('',*,*,#744,.F.);
#746=DIRECTION('',(0.,-1.,0.));
#747=VECTOR('',#746,1.);
#748=CARTESIAN_POINT('',(-27.2,68.,0.));
#749=LINE('',#748,#747);
#750=EDGE_CURVE('E678',#743,#725,#749,.T.);
#751=ORIENTED_EDGE('',*,*,#750,.T.);
#752=EDGE_LOOP('',(#729,#737,#745,#751));
#753=FACE_BOUND('',#752,.T.);
#754=ADVANCED_FACE('F921',(#697,#708,#719,#753),#686,.F.);
#755=CARTESIAN_POINT('',(0.,68.,0.));
#756=DIRECTION('',(0.,1.,0.));
#757=DIRECTION('',(0.,0.,1.));
#758=AXIS2_PLACEMENT_3D('',#755,#756,#757);
#759=PLANE('',#758);
#760=ORIENTED_EDGE('',*,*,#76,.T.);
#761=CARTESIAN_POINT('',(27.2,68.,-9.7));
#762=DIRECTION('',(0.,1.,0.));
#763=DIRECTION('',(0.,0.,1.));
#764=AXIS2_PLACEMENT_3D('',#761,#762,#763);
#765=CIRCLE('',#764,0.3);
#766=EDGE_CURVE('E661',#67,#97,#765,.T.);
#767=ORIENTED_EDGE('',*,*,#766,.T.);
#768=ORIENTED_EDGE('',*,*,#100,.T.);
#769=CARTESIAN_POINT('',(25.3,68.,-10.3));
#770=DIRECTION('',(0.,1.,0.));
#771=DIRECTION('',(0.,0.,1.));
#772=AXIS2_PLACEMENT_3D('',#769,#770,#771);
#773=CIRCLE('',#772,0.3);
#774=EDGE_CURVE('E685',#99,#137,#773,.F.);
#775=ORIENTED_EDGE('',*,*,#774,.T.);
#776=ORIENTED_EDGE('',*,*,#140,.T.);
#777=ORIENTED_EDGE('',*,*,#565,.T.);
#778=ORIENTED_EDGE('',*,*,#596,.T.);
#779=CARTESIAN_POINT('',(-25.3,68.,-10.3));
#780=DIRECTION('',(0.,1.,0.));
#781=DIRECTION('',(0.,0.,1.));
#782=AXIS2_PLACEMENT_3D('',#779,#780,#781);
#783=CIRCLE('',#782,0.3);
#784=EDGE_CURVE('E689',#589,#612,#783,.F.);
#785=ORIENTED_EDGE('',*,*,#784,.T.);
#786=ORIENTED_EDGE('',*,*,#615,.T.);
#787=CARTESIAN_POINT('',(-27.2,68.,-9.7));
#788=DIRECTION('',(0.,1.,0.));
#789=DIRECTION('',(0.,0.,1.));
#790=AXIS2_PLACEMENT_3D('',#787,#788,#789);
#791=CIRCLE('',#790,0.3);
#792=EDGE_CURVE('E659',#614,#652,#791,.T.);
#793=ORIENTED_EDGE('',*,*,#792,.T.);
#794=ORIENTED_EDGE('',*,*,#655,.T.);
#795=CARTESIAN_POINT('',(-27.2,68.,-0.3));
#796=DIRECTION('',(0.,1.,0.));
#797=DIRECTION('',(0.,0.,1.));
#798=AXIS2_PLACEMENT_3D('',#795,#796,#797);
#799=CIRCLE('',#798,0.3);
#800=EDGE_CURVE('E655',#654,#743,#799,.T.);
#801=ORIENTED_EDGE('',*,*,#800,.T.);
#802=ORIENTED_EDGE('',*,*,#744,.T.);
#803=CARTESIAN_POINT('',(27.2,68.,-0.3));
#804=DIRECTION('',(0.,1.,0.));
#805=DIRECTION('',(0.,0.,1.));
#806=AXIS2_PLACEMENT_3D('',#803,#804,#805);
#807=CIRCLE('',#806,0.3);
#808=EDGE_CURVE('E657',#735,#75,#807,.T.);
#809=ORIENTED_EDGE('',*,*,#808,.T.);
#810=EDGE_LOOP('',(#760,#767,#768,#775,#776,#777,#778,#785,#786,#793,#794,#801,#802,#809));
#811=FACE_BOUND('',#810,.T.);
#812=ADVANCED_FACE('F917',(#811),#759,.T.);
#813=CARTESIAN_POINT('',(0.,0.,0.));
#814=DIRECTION('',(0.,1.,0.));
#815=DIRECTION('',(0.,0.,1.));
#816=AXIS2_PLACEMENT_3D('',#813,#814,#815);
#817=PLANE('',#816);
#818=ORIENTED_EDGE('',*,*,#116,.F.);
#819=CARTESIAN_POINT('',(27.2,0.,-9.7));
#820=DIRECTION('',(0.,1.,0.));
#821=DIRECTION('',(0.,0.,1.));
#822=AXIS2_PLACEMENT_3D('',#819,#820,#821);
#823=CIRCLE('',#822,0.3);
#824=EDGE_CURVE('E648',#107,#59,#823,.F.);
#825=ORIENTED_EDGE('',*,*,#824,.T.);
#826=ORIENTED_EDGE('',*,*,#60,.F.);
#827=CARTESIAN_POINT('',(27.2,0.,-0.3));
#828=DIRECTION('',(0.,1.,0.));
#829=DIRECTION('',(0.,0.,1.));
#830=AXIS2_PLACEMENT_3D('',#827,#828,#829);
#831=CIRCLE('',#830,0.3);
#832=EDGE_CURVE('E644',#57,#727,#831,.F.);
#833=ORIENTED_EDGE('',*,*,#832,.T.);
#834=ORIENTED_EDGE('',*,*,#728,.F.);
#835=CARTESIAN_POINT('',(-27.2,0.,-0.3));
#836=DIRECTION('',(0.,1.,0.));
#837=DIRECTION('',(0.,0.,1.));
#838=AXIS2_PLACEMENT_3D('',#835,#836,#837);
#839=CIRCLE('',#838,0.3);
#840=EDGE_CURVE('E642',#725,#670,#839,.F.);
#841=ORIENTED_EDGE('',*,*,#840,.T.);
#842=ORIENTED_EDGE('',*,*,#671,.F.);
#843=CARTESIAN_POINT('',(-27.2,0.,-9.7));
#844=DIRECTION('',(0.,1.,0.));
#845=DIRECTION('',(0.,0.,1.));
#846=AXIS2_PLACEMENT_3D('',#843,#844,#845);
#847=CIRCLE('',#846,0.3);
#848=EDGE_CURVE('E646',#662,#630,#847,.F.);
#849=ORIENTED_EDGE('',*,*,#848,.T.);
#850=ORIENTED_EDGE('',*,*,#631,.F.);
#851=CARTESIAN_POINT('',(-25.3,0.,-10.3));
#852=DIRECTION('',(0.,1.,0.));
#853=DIRECTION('',(0.,0.,1.));
#854=AXIS2_PLACEMENT_3D('',#851,#852,#853);
#855=CIRCLE('',#854,0.3);
#856=EDGE_CURVE('E687',#622,#581,#855,.T.);
#857=ORIENTED_EDGE('',*,*,#856,.T.);
#858=ORIENTED_EDGE('',*,*,#582,.F.);
#859=ORIENTED_EDGE('',*,*,#551,.F.);
#860=ORIENTED_EDGE('',*,*,#156,.F.);
#861=CARTESIAN_POINT('',(25.3,0.,-10.3));
#862=DIRECTION('',(0.,1.,0.));
#863=DIRECTION('',(0.,0.,1.));
#864=AXIS2_PLACEMENT_3D('',#861,#862,#863);
#865=CIRCLE('',#864,0.3);
#866=EDGE_CURVE('E683',#147,#115,#865,.T.);
#867=ORIENTED_EDGE('',*,*,#866,.T.);
#868=EDGE_LOOP('',(#818,#825,#826,#833,#834,#841,#842,#849,#850,#857,#858,#859,#860,#867));
#869=FACE_BOUND('',#868,.T.);
#870=ADVANCED_FACE('F920',(#869),#817,.F.);
#871=CARTESIAN_POINT('',(27.2,68.,-9.7));
#872=DIRECTION('',(0.,-1.,0.));
#873=DIRECTION('',(0.,0.,-1.));
#874=AXIS2_PLACEMENT_3D('',#871,#872,#873);
#875=CYLINDRICAL_SURFACE('',#874,0.3);
#876=ORIENTED_EDGE('',*,*,#766,.F.);
#877=ORIENTED_EDGE('',*,*,#68,.F.);
#878=ORIENTED_EDGE('',*,*,#824,.F.);
#879=ORIENTED_EDGE('',*,*,#108,.F.);
#880=EDGE_LOOP('',(#876,#877,#878,#879));
#881=FACE_BOUND('',#880,.T.);
#882=ADVANCED_FACE('F925',(#881),#875,.T.);
#883=CARTESIAN_POINT('',(25.3,68.,-10.3));
#884=DIRECTION('',(0.,1.,0.));
#885=DIRECTION('',(0.,0.,1.));
#886=AXIS2_PLACEMENT_3D('',#883,#884,#885);
#887=CYLINDRICAL_SURFACE('',#886,0.3);
#888=ORIENTED_EDGE('',*,*,#774,.F.);
#889=ORIENTED_EDGE('',*,*,#122,.F.);
#890=ORIENTED_EDGE('',*,*,#866,.F.);
#891=ORIENTED_EDGE('',*,*,#148,.F.);
#892=EDGE_LOOP('',(#888,#889,#890,#891));
#893=FACE_BOUND('',#892,.T.);
#894=ADVANCED_FACE('F953',(#893),#887,.F.);
#895=CARTESIAN_POINT('',(-25.3,68.,-10.3));
#896=DIRECTION('',(0.,1.,0.));
#897=DIRECTION('',(0.,0.,1.));
#898=AXIS2_PLACEMENT_3D('',#895,#896,#897);
#899=CYLINDRICAL_SURFACE('',#898,0.3);
#900=ORIENTED_EDGE('',*,*,#784,.F.);
#901=ORIENTED_EDGE('',*,*,#590,.F.);
#902=ORIENTED_EDGE('',*,*,#856,.F.);
#903=ORIENTED_EDGE('',*,*,#623,.F.);
#904=EDGE_LOOP('',(#900,#901,#902,#903));
#905=FACE_BOUND('',#904,.T.);
#906=ADVANCED_FACE('F957',(#905),#899,.F.);
#907=CARTESIAN_POINT('',(-27.2,68.,-9.7));
#908=DIRECTION('',(0.,-1.,0.));
#909=DIRECTION('',(0.,0.,-1.));
#910=AXIS2_PLACEMENT_3D('',#907,#908,#909);
#911=CYLINDRICAL_SURFACE('',#910,0.3);
#912=ORIENTED_EDGE('',*,*,#792,.F.);
#913=ORIENTED_EDGE('',*,*,#637,.F.);
#914=ORIENTED_EDGE('',*,*,#848,.F.);
#915=ORIENTED_EDGE('',*,*,#663,.F.);
#916=EDGE_LOOP('',(#912,#913,#914,#915));
#917=FACE_BOUND('',#916,.T.);
#918=ADVANCED_FACE('F961',(#917),#911,.T.);
#919=CARTESIAN_POINT('',(27.2,68.,-0.3));
#920=DIRECTION('',(0.,-1.,0.));
#921=DIRECTION('',(0.,0.,-1.));
#922=AXIS2_PLACEMENT_3D('',#919,#920,#921);
#923=CYLINDRICAL_SURFACE('',#922,0.3);
#924=ORIENTED_EDGE('',*,*,#808,.F.);
#925=ORIENTED_EDGE('',*,*,#736,.F.);
#926=ORIENTED_EDGE('',*,*,#832,.F.);
#927=ORIENTED_EDGE('',*,*,#82,.F.);
#928=EDGE_LOOP('',(#924,#925,#926,#927));
#929=FACE_BOUND('',#928,.T.);
#930=ADVANCED_FACE('F965',(#929),#923,.T.);
#931=CARTESIAN_POINT('',(-27.2,68.,-0.3));
#932=DIRECTION('',(0.,-1.,0.));
#933=DIRECTION('',(0.,0.,-1.));
#934=AXIS2_PLACEMENT_3D('',#931,#932,#933);
#935=CYLINDRICAL_SURFACE('',#934,0.3);
#936=ORIENTED_EDGE('',*,*,#800,.F.);
#937=ORIENTED_EDGE('',*,*,#677,.F.);
#938=ORIENTED_EDGE('',*,*,#840,.F.);
#939=ORIENTED_EDGE('',*,*,#750,.F.);
#940=EDGE_LOOP('',(#936,#937,#938,#939));
#941=FACE_BOUND('',#940,.T.);
#942=ADVANCED_FACE('F915',(#941),#935,.T.);
#943=CARTESIAN_POINT('',(11.,62.5,0.));
#944=DIRECTION('',(0.,0.,-1.));
#945=DIRECTION('',(-1.,0.,0.));
#946=AXIS2_PLACEMENT_3D('',#943,#944,#945);
#947=CYLINDRICAL_SURFACE('',#946,3.);
#948=ORIENTED_EDGE('',*,*,#716,.F.);
#949=EDGE_LOOP('',(#948));
#950=FACE_BOUND('',#949,.T.);
#951=ORIENTED_EDGE('',*,*,#541,.T.);
#952=EDGE_LOOP('',(#951));
#953=FACE_BOUND('',#952,.T.);
#954=ADVANCED_FACE('F911',(#950,#953),#947,.F.);
#955=CARTESIAN_POINT('',(-11.,5.5,0.));
#956=DIRECTION('',(0.,0.,-1.));
#957=DIRECTION('',(-1.,0.,0.));
#958=AXIS2_PLACEMENT_3D('',#955,#956,#957);
#959=CYLINDRICAL_SURFACE('',#958,3.);
#960=ORIENTED_EDGE('',*,*,#705,.F.);
#961=EDGE_LOOP('',(#960));
#962=FACE_BOUND('',#961,.T.);
#963=ORIENTED_EDGE('',*,*,#530,.T.);
#964=EDGE_LOOP('',(#963));
#965=FACE_BOUND('',#964,.T.);
#966=ADVANCED_FACE('F907',(#962,#965),#959,.F.);
#967=CARTESIAN_POINT('',(0.,5.5,-10.));
#968=DIRECTION('',(0.,0.,1.));
#969=DIRECTION('',(1.,0.,0.));
#970=AXIS2_PLACEMENT_3D('',#967,#968,#969);
#971=PLANE('',#970);
#972=CARTESIAN_POINT('',(0.,5.5,-10.));
#973=DIRECTION('',(0.,0.,1.));
#974=DIRECTION('',(1.,0.,0.));
#975=AXIS2_PLACEMENT_3D('',#972,#973,#974);
#976=CIRCLE('',#975,3.);
#977=CARTESIAN_POINT('',(3.,5.5,-10.));
#978=VERTEX_POINT('',#977);
#979=EDGE_CURVE('E568',#978,#978,#976,.T.);
#980=ORIENTED_EDGE('',*,*,#979,.T.);
#981=EDGE_LOOP('',(#980));
#982=FACE_BOUND('',#981,.T.);
#983=ORIENTED_EDGE('',*,*,#42,.T.);
#984=EDGE_LOOP('',(#983));
#985=FACE_BOUND('',#984,.T.);
#986=ADVANCED_FACE('F910',(#982,#985),#971,.T.);
#987=CARTESIAN_POINT('',(0.,5.5,-10.));
#988=DIRECTION('',(0.,0.,1.));
#989=DIRECTION('',(1.,0.,0.));
#990=AXIS2_PLACEMENT_3D('',#987,#988,#989);
#991=CYLINDRICAL_SURFACE('',#990,3.);
#992=CARTESIAN_POINT('',(0.,5.5,-0.200000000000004));
#993=DIRECTION('',(0.,0.,-1.));
#994=DIRECTION('',(-1.,0.,0.));
#995=AXIS2_PLACEMENT_3D('',#992,#993,#994);
#996=CIRCLE('',#995,3.);
#997=CARTESIAN_POINT('',(-3.,5.5,-0.200000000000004));
#998=VERTEX_POINT('',#997);
#999=EDGE_CURVE('E691',#998,#998,#996,.F.);
#1000=ORIENTED_EDGE('',*,*,#999,.T.);
#1001=EDGE_LOOP('',(#1000));
#1002=FACE_BOUND('',#1001,.T.);
#1003=ORIENTED_EDGE('',*,*,#979,.F.);
#1004=EDGE_LOOP('',(#1003));
#1005=FACE_BOUND('',#1004,.T.);
#1006=ADVANCED_FACE('F905',(#1002,#1005),#991,.F.);
#1007=CARTESIAN_POINT('',(0.,5.5,-0.200000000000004));
#1008=DIRECTION('',(0.,0.,1.));
#1009=DIRECTION('',(1.,0.,0.));
#1010=AXIS2_PLACEMENT_3D('',#1007,#1008,#1009);
#1011=CONICAL_SURFACE('',#1010,3.,0.785398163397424);
#1012=ORIENTED_EDGE('',*,*,#694,.F.);
#1013=EDGE_LOOP('',(#1012));
#1014=FACE_BOUND('',#1013,.T.);
#1015=ORIENTED_EDGE('',*,*,#999,.F.);
#1016=EDGE_LOOP('',(#1015));
#1017=FACE_BOUND('',#1016,.T.);
#1018=ADVANCED_FACE('F35',(#1014,#1017),#1011,.F.);
#1019=CARTESIAN_POINT('',(14.075,48.35,-25.11875));
#1020=DIRECTION('',(-1.,0.,0.));
#1021=DIRECTION('',(0.,1.,0.));
#1022=AXIS2_PLACEMENT_3D('',#1019,#1020,#1021);
#1023=PLANE('',#1022);
#1024=ORIENTED_EDGE('',*,*,#397,.T.);
#1025=DIRECTION('',(0.,0.,-1.));
#1026=VECTOR('',#1025,1.);
#1027=CARTESIAN_POINT('',(14.075,25.0737901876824,-25.11875));
#1028=LINE('',#1027,#1026);
#1029=CARTESIAN_POINT('',(14.075,25.0737901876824,-23.58125));
#1030=VERTEX_POINT('',#1029);
#1031=EDGE_CURVE('E494',#1030,#388,#1028,.T.);
#1032=ORIENTED_EDGE('',*,*,#1031,.F.);
#1033=DIRECTION('',(0.,-1.,0.));
#1034=VECTOR('',#1033,1.);
#1035=CARTESIAN_POINT('',(14.075,48.35,-23.58125));
#1036=LINE('',#1035,#1034);
#1037=CARTESIAN_POINT('',(14.075,42.9262098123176,-23.58125));
#1038=VERTEX_POINT('',#1037);
#1039=EDGE_CURVE('E470',#1038,#1030,#1036,.T.);
#1040=ORIENTED_EDGE('',*,*,#1039,.F.);
#1041=DIRECTION('',(0.,0.,1.));
#1042=VECTOR('',#1041,1.);
#1043=CARTESIAN_POINT('',(14.075,42.9262098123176,-25.11875));
#1044=LINE('',#1043,#1042);
#1045=EDGE_CURVE('E497',#396,#1038,#1044,.T.);
#1046=ORIENTED_EDGE('',*,*,#1045,.F.);
#1047=EDGE_LOOP('',(#1024,#1032,#1040,#1046));
#1048=FACE_BOUND('',#1047,.T.);
#1049=ADVANCED_FACE('F1040',(#1048),#1023,.T.);
#1050=CARTESIAN_POINT('',(16.125,19.65,-25.11875));
#1051=DIRECTION('',(-1.,0.,0.));
#1052=DIRECTION('',(0.,1.,0.));
#1053=AXIS2_PLACEMENT_3D('',#1050,#1051,#1052);
#1054=PLANE('',#1053);
#1055=ORIENTED_EDGE('',*,*,#371,.T.);
#1056=DIRECTION('',(0.,0.,1.));
#1057=VECTOR('',#1056,1.);
#1058=CARTESIAN_POINT('',(16.125,14.525,-25.11875));
#1059=LINE('',#1058,#1057);
#1060=CARTESIAN_POINT('',(16.125,14.525,-23.58125));
#1061=VERTEX_POINT('',#1060);
#1062=EDGE_CURVE('E542',#1061,#362,#1059,.F.);
#1063=ORIENTED_EDGE('',*,*,#1062,.F.);
#1064=DIRECTION('',(0.,-1.,0.));
#1065=VECTOR('',#1064,1.);
#1066=CARTESIAN_POINT('',(16.125,19.65,-23.58125));
#1067=LINE('',#1066,#1065);
#1068=CARTESIAN_POINT('',(16.125,18.9237901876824,-23.58125));
#1069=VERTEX_POINT('',#1068);
#1070=EDGE_CURVE('E473',#1069,#1061,#1067,.T.);
#1071=ORIENTED_EDGE('',*,*,#1070,.F.);
#1072=DIRECTION('',(0.,0.,-1.));
#1073=VECTOR('',#1072,1.);
#1074=CARTESIAN_POINT('',(16.125,18.9237901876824,-25.11875));
#1075=LINE('',#1074,#1073);
#1076=EDGE_CURVE('E545',#370,#1069,#1075,.F.);
#1077=ORIENTED_EDGE('',*,*,#1076,.F.);
#1078=EDGE_LOOP('',(#1055,#1063,#1071,#1077));
#1079=FACE_BOUND('',#1078,.T.);
#1080=ADVANCED_FACE('F1048',(#1079),#1054,.T.);
#1081=CARTESIAN_POINT('',(16.125,12.475,-25.11875));
#1082=DIRECTION('',(0.,1.,0.));
#1083=DIRECTION('',(0.,0.,-1.));
#1084=AXIS2_PLACEMENT_3D('',#1081,#1082,#1083);
#1085=PLANE('',#1084);
#1086=ORIENTED_EDGE('',*,*,#354,.T.);
#1087=DIRECTION('',(0.,0.,1.));
#1088=VECTOR('',#1087,1.);
#1089=CARTESIAN_POINT('',(7.92499999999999,12.475,-25.11875));
#1090=LINE('',#1089,#1088);
#1091=CARTESIAN_POINT('',(7.92499999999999,12.475,-23.58125));
#1092=VERTEX_POINT('',#1091);
#1093=EDGE_CURVE('E550',#1092,#353,#1090,.F.);
#1094=ORIENTED_EDGE('',*,*,#1093,.F.);
#1095=DIRECTION('',(-1.,0.,0.));
#1096=VECTOR('',#1095,1.);
#1097=CARTESIAN_POINT('',(16.125,12.475,-23.58125));
#1098=LINE('',#1097,#1096);
#1099=CARTESIAN_POINT('',(14.075,12.475,-23.58125));
#1100=VERTEX_POINT('',#1099);
#1101=EDGE_CURVE('E476',#1100,#1092,#1098,.T.);
#1102=ORIENTED_EDGE('',*,*,#1101,.F.);
#1103=DIRECTION('',(0.,0.,1.));
#1104=VECTOR('',#1103,1.);
#1105=CARTESIAN_POINT('',(14.075,12.475,-25.11875));
#1106=LINE('',#1105,#1104);
#1107=EDGE_CURVE('E553',#351,#1100,#1106,.T.);
#1108=ORIENTED_EDGE('',*,*,#1107,.F.);
#1109=EDGE_LOOP('',(#1086,#1094,#1102,#1108));
#1110=FACE_BOUND('',#1109,.T.);
#1111=ADVANCED_FACE('F1056',(#1110),#1085,.T.);
#1112=CARTESIAN_POINT('',(5.87499999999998,19.65,-25.11875));
#1113=DIRECTION('',(1.,0.,0.));
#1114=DIRECTION('',(0.,-1.,0.));
#1115=AXIS2_PLACEMENT_3D('',#1112,#1113,#1114);
#1116=PLANE('',#1115);
#1117=ORIENTED_EDGE('',*,*,#509,.T.);
#1118=DIRECTION('',(0.,0.,1.));
#1119=VECTOR('',#1118,1.);
#1120=CARTESIAN_POINT('',(5.87499999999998,18.9237901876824,-25.11875));
#1121=LINE('',#1120,#1119);
#1122=CARTESIAN_POINT('',(5.87499999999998,18.9237901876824,-23.58125));
#1123=VERTEX_POINT('',#1122);
#1124=EDGE_CURVE('E555',#1123,#500,#1121,.F.);
#1125=ORIENTED_EDGE('',*,*,#1124,.F.);
#1126=DIRECTION('',(0.,1.,0.));
#1127=VECTOR('',#1126,1.);
#1128=CARTESIAN_POINT('',(5.87499999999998,19.65,-23.58125));
#1129=LINE('',#1128,#1127);
#1130=CARTESIAN_POINT('',(5.87499999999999,14.525,-23.58125));
#1131=VERTEX_POINT('',#1130);
#1132=EDGE_CURVE('E479',#1131,#1123,#1129,.T.);
#1133=ORIENTED_EDGE('',*,*,#1132,.F.);
#1134=DIRECTION('',(0.,0.,1.));
#1135=VECTOR('',#1134,1.);
#1136=CARTESIAN_POINT('',(5.87499999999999,14.525,-25.11875));
#1137=LINE('',#1136,#1135);
#1138=EDGE_CURVE('E558',#508,#1131,#1137,.T.);
#1139=ORIENTED_EDGE('',*,*,#1138,.F.);
#1140=EDGE_LOOP('',(#1117,#1125,#1133,#1139));
#1141=FACE_BOUND('',#1140,.T.);
#1142=ADVANCED_FACE('F1064',(#1141),#1116,.T.);
#1143=CARTESIAN_POINT('',(7.92500000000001,48.35,-25.11875));
#1144=DIRECTION('',(1.,0.,0.));
#1145=DIRECTION('',(0.,-1.,0.));
#1146=AXIS2_PLACEMENT_3D('',#1143,#1144,#1145);
#1147=PLANE('',#1146);
#1148=ORIENTED_EDGE('',*,*,#483,.T.);
#1149=DIRECTION('',(0.,0.,-1.));
#1150=VECTOR('',#1149,1.);
#1151=CARTESIAN_POINT('',(7.92500000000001,42.9262098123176,-25.11875));
#1152=LINE('',#1151,#1150);
#1153=CARTESIAN_POINT('',(7.92500000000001,42.9262098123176,-23.58125));
#1154=VERTEX_POINT('',#1153);
#1155=EDGE_CURVE('E501',#1154,#474,#1152,.T.);
#1156=ORIENTED_EDGE('',*,*,#1155,.F.);
#1157=DIRECTION('',(0.,1.,0.));
#1158=VECTOR('',#1157,1.);
#1159=CARTESIAN_POINT('',(7.92500000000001,48.35,-23.58125));
#1160=LINE('',#1159,#1158);
#1161=CARTESIAN_POINT('',(7.925,25.0737901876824,-23.58125));
#1162=VERTEX_POINT('',#1161);
#1163=EDGE_CURVE('E482',#1162,#1154,#1160,.T.);
#1164=ORIENTED_EDGE('',*,*,#1163,.F.);
#1165=DIRECTION('',(0.,0.,1.));
#1166=VECTOR('',#1165,1.);
#1167=CARTESIAN_POINT('',(7.925,25.0737901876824,-25.11875));
#1168=LINE('',#1167,#1166);
#1169=EDGE_CURVE('E499',#482,#1162,#1168,.T.);
#1170=ORIENTED_EDGE('',*,*,#1169,.F.);
#1171=EDGE_LOOP('',(#1148,#1156,#1164,#1170));
#1172=FACE_BOUND('',#1171,.T.);
#1173=ADVANCED_FACE('F1072',(#1172),#1147,.T.);
#1174=CARTESIAN_POINT('',(5.87500000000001,55.525,-25.11875));
#1175=DIRECTION('',(1.,0.,0.));
#1176=DIRECTION('',(0.,0.,-1.));
#1177=AXIS2_PLACEMENT_3D('',#1174,#1175,#1176);
#1178=PLANE('',#1177);
#1179=ORIENTED_EDGE('',*,*,#457,.T.);
#1180=DIRECTION('',(0.,0.,1.));
#1181=VECTOR('',#1180,1.);
#1182=CARTESIAN_POINT('',(5.87500000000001,53.475,-25.11875));
#1183=LINE('',#1182,#1181);
#1184=CARTESIAN_POINT('',(5.87500000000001,53.475,-23.58125));
#1185=VERTEX_POINT('',#1184);
#1186=EDGE_CURVE('E56',#1185,#448,#1183,.F.);
#1187=ORIENTED_EDGE('',*,*,#1186,.F.);
#1188=DIRECTION('',(0.,1.,0.));
#1189=VECTOR('',#1188,1.);
#1190=CARTESIAN_POINT('',(5.87500000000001,55.525,-23.58125));
#1191=LINE('',#1190,#1189);
#1192=CARTESIAN_POINT('',(5.87500000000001,49.0762098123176,-23.58125));
#1193=VERTEX_POINT('',#1192);
#1194=EDGE_CURVE('E485',#1193,#1185,#1191,.T.);
#1195=ORIENTED_EDGE('',*,*,#1194,.F.);
#1196=DIRECTION('',(0.,0.,-1.));
#1197=VECTOR('',#1196,1.);
#1198=CARTESIAN_POINT('',(5.875,49.0762098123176,-25.11875));
#1199=LINE('',#1198,#1197);
#1200=EDGE_CURVE('E563',#456,#1193,#1199,.F.);
#1201=ORIENTED_EDGE('',*,*,#1200,.F.);
#1202=EDGE_LOOP('',(#1179,#1187,#1195,#1201));
#1203=FACE_BOUND('',#1202,.T.);
#1204=ADVANCED_FACE('F1080',(#1203),#1178,.T.);
#1205=CARTESIAN_POINT('',(16.125,55.525,-25.11875));
#1206=DIRECTION('',(0.,-1.,0.));
#1207=DIRECTION('',(0.,0.,1.));
#1208=AXIS2_PLACEMENT_3D('',#1205,#1206,#1207);
#1209=PLANE('',#1208);
#1210=ORIENTED_EDGE('',*,*,#440,.T.);
#1211=DIRECTION('',(0.,0.,1.));
#1212=VECTOR('',#1211,1.);
#1213=CARTESIAN_POINT('',(14.075,55.525,-25.11875));
#1214=LINE('',#1213,#1212);
#1215=CARTESIAN_POINT('',(14.075,55.525,-23.58125));
#1216=VERTEX_POINT('',#1215);
#1217=EDGE_CURVE('E537',#1216,#431,#1214,.F.);
#1218=ORIENTED_EDGE('',*,*,#1217,.F.);
#1219=DIRECTION('',(1.,0.,0.));
#1220=VECTOR('',#1219,1.);
#1221=CARTESIAN_POINT('',(16.125,55.525,-23.58125));
#1222=LINE('',#1221,#1220);
#1223=CARTESIAN_POINT('',(7.92500000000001,55.525,-23.58125));
#1224=VERTEX_POINT('',#1223);
#1225=EDGE_CURVE('E488',#1224,#1216,#1222,.T.);
#1226=ORIENTED_EDGE('',*,*,#1225,.F.);
#1227=DIRECTION('',(0.,0.,1.));
#1228=VECTOR('',#1227,1.);
#1229=CARTESIAN_POINT('',(7.92500000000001,55.525,-25.11875));
#1230=LINE('',#1229,#1228);
#1231=EDGE_CURVE('E535',#439,#1224,#1230,.T.);
#1232=ORIENTED_EDGE('',*,*,#1231,.F.);
#1233=EDGE_LOOP('',(#1210,#1218,#1226,#1232));
#1234=FACE_BOUND('',#1233,.T.);
#1235=ADVANCED_FACE('F1088',(#1234),#1209,.T.);
#1236=CARTESIAN_POINT('',(16.125,55.525,-25.11875));
#1237=DIRECTION('',(-1.,0.,0.));
#1238=DIRECTION('',(0.,0.,1.));
#1239=AXIS2_PLACEMENT_3D('',#1236,#1237,#1238);
#1240=PLANE('',#1239);
#1241=ORIENTED_EDGE('',*,*,#423,.T.);
#1242=DIRECTION('',(0.,0.,1.));
#1243=VECTOR('',#1242,1.);
#1244=CARTESIAN_POINT('',(16.125,49.0762098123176,-25.11875));
#1245=LINE('',#1244,#1243);
#1246=CARTESIAN_POINT('',(16.125,49.0762098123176,-23.58125));
#1247=VERTEX_POINT('',#1246);
#1248=EDGE_CURVE('E514',#1247,#414,#1245,.F.);
#1249=ORIENTED_EDGE('',*,*,#1248,.F.);
#1250=DIRECTION('',(0.,-1.,0.));
#1251=VECTOR('',#1250,1.);
#1252=CARTESIAN_POINT('',(16.125,55.525,-23.58125));
#1253=LINE('',#1252,#1251);
#1254=CARTESIAN_POINT('',(16.125,53.475,-23.58125));
#1255=VERTEX_POINT('',#1254);
#1256=EDGE_CURVE('E491',#1255,#1247,#1253,.T.);
#1257=ORIENTED_EDGE('',*,*,#1256,.F.);
#1258=DIRECTION('',(0.,0.,1.));
#1259=VECTOR('',#1258,1.);
#1260=CARTESIAN_POINT('',(16.125,53.475,-25.11875));
#1261=LINE('',#1260,#1259);
#1262=EDGE_CURVE('E517',#422,#1255,#1261,.T.);
#1263=ORIENTED_EDGE('',*,*,#1262,.F.);
#1264=EDGE_LOOP('',(#1241,#1249,#1257,#1263));
#1265=FACE_BOUND('',#1264,.T.);
#1266=ADVANCED_FACE('F1096',(#1265),#1240,.T.);
#1267=CARTESIAN_POINT('',(22.275,42.9262098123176,-25.11875));
#1268=DIRECTION('',(0.,0.,1.));
#1269=DIRECTION('',(1.,0.,0.));
#1270=AXIS2_PLACEMENT_3D('',#1267,#1268,#1269);
#1271=CYLINDRICAL_SURFACE('',#1270,8.2);
#1272=ORIENTED_EDGE('',*,*,#406,.T.);
#1273=ORIENTED_EDGE('',*,*,#1045,.T.);
#1274=CARTESIAN_POINT('',(22.275,42.9262098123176,-23.58125));
#1275=DIRECTION('',(0.,0.,1.));
#1276=DIRECTION('',(1.,0.,0.));
#1277=AXIS2_PLACEMENT_3D('',#1274,#1275,#1276);
#1278=CIRCLE('',#1277,8.2);
#1279=CARTESIAN_POINT('',(15.715,47.8462098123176,-23.58125));
#1280=VERTEX_POINT('',#1279);
#1281=EDGE_CURVE('E504',#1038,#1280,#1278,.F.);
#1282=ORIENTED_EDGE('',*,*,#1281,.T.);
#1283=DIRECTION('',(0.,0.,1.));
#1284=VECTOR('',#1283,1.);
#1285=CARTESIAN_POINT('',(15.715,47.8462098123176,-25.11875));
#1286=LINE('',#1285,#1284);
#1287=EDGE_CURVE('E540',#405,#1280,#1286,.T.);
#1288=ORIENTED_EDGE('',*,*,#1287,.F.);
#1289=EDGE_LOOP('',(#1272,#1273,#1282,#1288));
#1290=FACE_BOUND('',#1289,.T.);
#1291=ADVANCED_FACE('F1104',(#1290),#1271,.T.);
#1292=CARTESIAN_POINT('',(-0.27499999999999,42.9262098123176,-25.11875));
#1293=DIRECTION('',(0.,0.,-1.));
#1294=DIRECTION('',(-1.,0.,0.));
#1295=AXIS2_PLACEMENT_3D('',#1292,#1293,#1294);
#1296=CYLINDRICAL_SURFACE('',#1295,8.2);
#1297=ORIENTED_EDGE('',*,*,#475,.T.);
#1298=DIRECTION('',(0.,0.,-1.));
#1299=VECTOR('',#1298,1.);
#1300=CARTESIAN_POINT('',(6.28500000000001,47.8462098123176,-25.11875));
#1301=LINE('',#1300,#1299);
#1302=CARTESIAN_POINT('',(6.28500000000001,47.8462098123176,-23.58125));
#1303=VERTEX_POINT('',#1302);
#1304=EDGE_CURVE('E565',#1303,#465,#1301,.T.);
#1305=ORIENTED_EDGE('',*,*,#1304,.F.);
#1306=CARTESIAN_POINT('',(-0.274999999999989,42.9262098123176,-23.58125));
#1307=DIRECTION('',(0.,0.,1.));
#1308=DIRECTION('',(1.,0.,0.));
#1309=AXIS2_PLACEMENT_3D('',#1306,#1307,#1308);
#1310=CIRCLE('',#1309,8.2);
#1311=EDGE_CURVE('E507',#1303,#1154,#1310,.F.);
#1312=ORIENTED_EDGE('',*,*,#1311,.T.);
#1313=ORIENTED_EDGE('',*,*,#1155,.T.);
#1314=EDGE_LOOP('',(#1297,#1305,#1312,#1313));
#1315=FACE_BOUND('',#1314,.T.);
#1316=ADVANCED_FACE('F1112',(#1315),#1296,.T.);
#1317=CARTESIAN_POINT('',(-0.275000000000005,25.0737901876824,-25.11875));
#1318=DIRECTION('',(0.,0.,1.));
#1319=DIRECTION('',(1.,0.,0.));
#1320=AXIS2_PLACEMENT_3D('',#1317,#1318,#1319);
#1321=CYLINDRICAL_SURFACE('',#1320,8.2);
#1322=ORIENTED_EDGE('',*,*,#492,.T.);
#1323=ORIENTED_EDGE('',*,*,#1169,.T.);
#1324=CARTESIAN_POINT('',(-0.275000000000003,25.0737901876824,-23.58125));
#1325=DIRECTION('',(0.,0.,1.));
#1326=DIRECTION('',(1.,0.,0.));
#1327=AXIS2_PLACEMENT_3D('',#1324,#1325,#1326);
#1328=CIRCLE('',#1327,8.2);
#1329=CARTESIAN_POINT('',(6.28499999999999,20.1537901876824,-23.58125));
#1330=VERTEX_POINT('',#1329);
#1331=EDGE_CURVE('E509',#1162,#1330,#1328,.F.);
#1332=ORIENTED_EDGE('',*,*,#1331,.T.);
#1333=DIRECTION('',(0.,0.,1.));
#1334=VECTOR('',#1333,1.);
#1335=CARTESIAN_POINT('',(6.28499999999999,20.1537901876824,-25.11875));
#1336=LINE('',#1335,#1334);
#1337=EDGE_CURVE('E560',#491,#1330,#1336,.T.);
#1338=ORIENTED_EDGE('',*,*,#1337,.F.);
#1339=EDGE_LOOP('',(#1322,#1323,#1332,#1338));
#1340=FACE_BOUND('',#1339,.T.);
#1341=ADVANCED_FACE('F1120',(#1340),#1321,.T.);
#1342=CARTESIAN_POINT('',(22.275,25.0737901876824,-25.11875));
#1343=DIRECTION('',(0.,0.,-1.));
#1344=DIRECTION('',(-1.,0.,0.));
#1345=AXIS2_PLACEMENT_3D('',#1342,#1343,#1344);
#1346=CYLINDRICAL_SURFACE('',#1345,8.2);
#1347=ORIENTED_EDGE('',*,*,#389,.T.);
#1348=DIRECTION('',(0.,0.,-1.));
#1349=VECTOR('',#1348,1.);
#1350=CARTESIAN_POINT('',(15.715,20.1537901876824,-25.11875));
#1351=LINE('',#1350,#1349);
#1352=CARTESIAN_POINT('',(15.715,20.1537901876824,-23.58125));
#1353=VERTEX_POINT('',#1352);
#1354=EDGE_CURVE('E547',#1353,#379,#1351,.T.);
#1355=ORIENTED_EDGE('',*,*,#1354,.F.);
#1356=CARTESIAN_POINT('',(22.275,25.0737901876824,-23.58125));
#1357=DIRECTION('',(0.,0.,1.));
#1358=DIRECTION('',(1.,0.,0.));
#1359=AXIS2_PLACEMENT_3D('',#1356,#1357,#1358);
#1360=CIRCLE('',#1359,8.2);
#1361=EDGE_CURVE('E512',#1353,#1030,#1360,.F.);
#1362=ORIENTED_EDGE('',*,*,#1361,.T.);
#1363=ORIENTED_EDGE('',*,*,#1031,.T.);
#1364=EDGE_LOOP('',(#1347,#1355,#1362,#1363));
#1365=FACE_BOUND('',#1364,.T.);
#1366=ADVANCED_FACE('F1128',(#1365),#1346,.T.);
#1367=CARTESIAN_POINT('',(14.075,53.475,-25.11875));
#1368=DIRECTION('',(0.,0.,1.));
#1369=DIRECTION('',(1.,0.,0.));
#1370=AXIS2_PLACEMENT_3D('',#1367,#1368,#1369);
#1371=CYLINDRICAL_SURFACE('',#1370,2.05);
#1372=ORIENTED_EDGE('',*,*,#1262,.T.);
#1373=CARTESIAN_POINT('',(14.075,53.475,-23.58125));
#1374=DIRECTION('',(0.,0.,1.));
#1375=DIRECTION('',(1.,0.,0.));
#1376=AXIS2_PLACEMENT_3D('',#1373,#1374,#1375);
#1377=CIRCLE('',#1376,2.05);
#1378=EDGE_CURVE('E533',#1255,#1216,#1377,.T.);
#1379=ORIENTED_EDGE('',*,*,#1378,.T.);
#1380=ORIENTED_EDGE('',*,*,#1217,.T.);
#1381=ORIENTED_EDGE('',*,*,#432,.F.);
#1382=EDGE_LOOP('',(#1372,#1379,#1380,#1381));
#1383=FACE_BOUND('',#1382,.T.);
#1384=ADVANCED_FACE('F1136',(#1383),#1371,.F.);
#1385=CARTESIAN_POINT('',(14.075,49.0762098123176,-25.11875));
#1386=DIRECTION('',(0.,0.,1.));
#1387=DIRECTION('',(1.,0.,0.));
#1388=AXIS2_PLACEMENT_3D('',#1385,#1386,#1387);
#1389=CYLINDRICAL_SURFACE('',#1388,2.05);
#1390=ORIENTED_EDGE('',*,*,#1287,.T.);
#1391=CARTESIAN_POINT('',(14.075,49.0762098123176,-23.58125));
#1392=DIRECTION('',(0.,0.,1.));
#1393=DIRECTION('',(1.,0.,0.));
#1394=AXIS2_PLACEMENT_3D('',#1391,#1392,#1393);
#1395=CIRCLE('',#1394,2.05);
#1396=EDGE_CURVE('E531',#1280,#1247,#1395,.T.);
#1397=ORIENTED_EDGE('',*,*,#1396,.T.);
#1398=ORIENTED_EDGE('',*,*,#1248,.T.);
#1399=ORIENTED_EDGE('',*,*,#415,.F.);
#1400=EDGE_LOOP('',(#1390,#1397,#1398,#1399));
#1401=FACE_BOUND('',#1400,.T.);
#1402=ADVANCED_FACE('F1144',(#1401),#1389,.F.);
#1403=CARTESIAN_POINT('',(14.075,18.9237901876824,-25.11875));
#1404=DIRECTION('',(0.,0.,-1.));
#1405=DIRECTION('',(-1.,0.,0.));
#1406=AXIS2_PLACEMENT_3D('',#1403,#1404,#1405);
#1407=CYLINDRICAL_SURFACE('',#1406,2.05);
#1408=ORIENTED_EDGE('',*,*,#1076,.T.);
#1409=CARTESIAN_POINT('',(14.075,18.9237901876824,-23.58125));
#1410=DIRECTION('',(0.,0.,1.));
#1411=DIRECTION('',(1.,0.,0.));
#1412=AXIS2_PLACEMENT_3D('',#1409,#1410,#1411);
#1413=CIRCLE('',#1412,2.05);
#1414=EDGE_CURVE('E529',#1069,#1353,#1413,.T.);
#1415=ORIENTED_EDGE('',*,*,#1414,.T.);
#1416=ORIENTED_EDGE('',*,*,#1354,.T.);
#1417=ORIENTED_EDGE('',*,*,#380,.F.);
#1418=EDGE_LOOP('',(#1408,#1415,#1416,#1417));
#1419=FACE_BOUND('',#1418,.T.);
#1420=ADVANCED_FACE('F1152',(#1419),#1407,.F.);
#1421=CARTESIAN_POINT('',(14.075,14.525,-25.11875));
#1422=DIRECTION('',(0.,0.,1.));
#1423=DIRECTION('',(1.,0.,0.));
#1424=AXIS2_PLACEMENT_3D('',#1421,#1422,#1423);
#1425=CYLINDRICAL_SURFACE('',#1424,2.05);
#1426=ORIENTED_EDGE('',*,*,#1107,.T.);
#1427=CARTESIAN_POINT('',(14.075,14.525,-23.58125));
#1428=DIRECTION('',(0.,0.,1.));
#1429=DIRECTION('',(1.,0.,0.));
#1430=AXIS2_PLACEMENT_3D('',#1427,#1428,#1429);
#1431=CIRCLE('',#1430,2.05);
#1432=EDGE_CURVE('E527',#1100,#1061,#1431,.T.);
#1433=ORIENTED_EDGE('',*,*,#1432,.T.);
#1434=ORIENTED_EDGE('',*,*,#1062,.T.);
#1435=ORIENTED_EDGE('',*,*,#363,.F.);
#1436=EDGE_LOOP('',(#1426,#1433,#1434,#1435));
#1437=FACE_BOUND('',#1436,.T.);
#1438=ADVANCED_FACE('F1160',(#1437),#1425,.F.);
#1439=CARTESIAN_POINT('',(7.92499999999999,14.525,-25.11875));
#1440=DIRECTION('',(0.,0.,1.));
#1441=DIRECTION('',(1.,0.,0.));
#1442=AXIS2_PLACEMENT_3D('',#1439,#1440,#1441);
#1443=CYLINDRICAL_SURFACE('',#1442,2.05);
#1444=ORIENTED_EDGE('',*,*,#1138,.T.);
#1445=CARTESIAN_POINT('',(7.92499999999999,14.525,-23.58125));
#1446=DIRECTION('',(0.,0.,1.));
#1447=DIRECTION('',(1.,0.,0.));
#1448=AXIS2_PLACEMENT_3D('',#1445,#1446,#1447);
#1449=CIRCLE('',#1448,2.05);
#1450=EDGE_CURVE('E525',#1131,#1092,#1449,.T.);
#1451=ORIENTED_EDGE('',*,*,#1450,.T.);
#1452=ORIENTED_EDGE('',*,*,#1093,.T.);
#1453=ORIENTED_EDGE('',*,*,#516,.F.);
#1454=EDGE_LOOP('',(#1444,#1451,#1452,#1453));
#1455=FACE_BOUND('',#1454,.T.);
#1456=ADVANCED_FACE('F1168',(#1455),#1443,.F.);
#1457=CARTESIAN_POINT('',(7.92499999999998,18.9237901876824,-25.11875));
#1458=DIRECTION('',(0.,0.,1.));
#1459=DIRECTION('',(1.,0.,0.));
#1460=AXIS2_PLACEMENT_3D('',#1457,#1458,#1459);
#1461=CYLINDRICAL_SURFACE('',#1460,2.05);
#1462=ORIENTED_EDGE('',*,*,#1337,.T.);
#1463=CARTESIAN_POINT('',(7.92499999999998,18.9237901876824,-23.58125));
#1464=DIRECTION('',(0.,0.,1.));
#1465=DIRECTION('',(1.,0.,0.));
#1466=AXIS2_PLACEMENT_3D('',#1463,#1464,#1465);
#1467=CIRCLE('',#1466,2.05);
#1468=EDGE_CURVE('E523',#1330,#1123,#1467,.T.);
#1469=ORIENTED_EDGE('',*,*,#1468,.T.);
#1470=ORIENTED_EDGE('',*,*,#1124,.T.);
#1471=ORIENTED_EDGE('',*,*,#501,.F.);
#1472=EDGE_LOOP('',(#1462,#1469,#1470,#1471));
#1473=FACE_BOUND('',#1472,.T.);
#1474=ADVANCED_FACE('F1176',(#1473),#1461,.F.);
#1475=CARTESIAN_POINT('',(7.92500000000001,49.0762098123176,-25.11875));
#1476=DIRECTION('',(0.,0.,-1.));
#1477=DIRECTION('',(-1.,0.,0.));
#1478=AXIS2_PLACEMENT_3D('',#1475,#1476,#1477);
#1479=CYLINDRICAL_SURFACE('',#1478,2.05);
#1480=ORIENTED_EDGE('',*,*,#1200,.T.);
#1481=CARTESIAN_POINT('',(7.92500000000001,49.0762098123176,-23.58125));
#1482=DIRECTION('',(0.,0.,1.));
#1483=DIRECTION('',(1.,0.,0.));
#1484=AXIS2_PLACEMENT_3D('',#1481,#1482,#1483);
#1485=CIRCLE('',#1484,2.05);
#1486=EDGE_CURVE('E521',#1193,#1303,#1485,.T.);
#1487=ORIENTED_EDGE('',*,*,#1486,.T.);
#1488=ORIENTED_EDGE('',*,*,#1304,.T.);
#1489=ORIENTED_EDGE('',*,*,#466,.F.);
#1490=EDGE_LOOP('',(#1480,#1487,#1488,#1489));
#1491=FACE_BOUND('',#1490,.T.);
#1492=ADVANCED_FACE('F1184',(#1491),#1479,.F.);
#1493=CARTESIAN_POINT('',(7.92500000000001,53.475,-25.11875));
#1494=DIRECTION('',(0.,0.,1.));
#1495=DIRECTION('',(1.,0.,0.));
#1496=AXIS2_PLACEMENT_3D('',#1493,#1494,#1495);
#1497=CYLINDRICAL_SURFACE('',#1496,2.05);
#1498=ORIENTED_EDGE('',*,*,#1231,.T.);
#1499=CARTESIAN_POINT('',(7.92500000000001,53.475,-23.58125));
#1500=DIRECTION('',(0.,0.,1.));
#1501=DIRECTION('',(1.,0.,0.));
#1502=AXIS2_PLACEMENT_3D('',#1499,#1500,#1501);
#1503=CIRCLE('',#1502,2.05);
#1504=EDGE_CURVE('E519',#1224,#1185,#1503,.T.);
#1505=ORIENTED_EDGE('',*,*,#1504,.T.);
#1506=ORIENTED_EDGE('',*,*,#1186,.T.);
#1507=ORIENTED_EDGE('',*,*,#449,.F.);
#1508=EDGE_LOOP('',(#1498,#1505,#1506,#1507));
#1509=FACE_BOUND('',#1508,.T.);
#1510=ADVANCED_FACE('F1192',(#1509),#1497,.F.);
#1511=CARTESIAN_POINT('',(11.,39.125,-23.58125));
#1512=DIRECTION('',(0.,0.,1.));
#1513=DIRECTION('',(1.,0.,0.));
#1514=AXIS2_PLACEMENT_3D('',#1511,#1512,#1513);
#1515=PLANE('',#1514);
#1516=ORIENTED_EDGE('',*,*,#1256,.T.);
#1517=ORIENTED_EDGE('',*,*,#1396,.F.);
#1518=ORIENTED_EDGE('',*,*,#1281,.F.);
#1519=ORIENTED_EDGE('',*,*,#1039,.T.);
#1520=ORIENTED_EDGE('',*,*,#1361,.F.);
#1521=ORIENTED_EDGE('',*,*,#1414,.F.);
#1522=ORIENTED_EDGE('',*,*,#1070,.T.);
#1523=ORIENTED_EDGE('',*,*,#1432,.F.);
#1524=ORIENTED_EDGE('',*,*,#1101,.T.);
#1525=ORIENTED_EDGE('',*,*,#1450,.F.);
#1526=ORIENTED_EDGE('',*,*,#1132,.T.);
#1527=ORIENTED_EDGE('',*,*,#1468,.F.);
#1528=ORIENTED_EDGE('',*,*,#1331,.F.);
#1529=ORIENTED_EDGE('',*,*,#1163,.T.);
#1530=ORIENTED_EDGE('',*,*,#1311,.F.);
#1531=ORIENTED_EDGE('',*,*,#1486,.F.);
#1532=ORIENTED_EDGE('',*,*,#1194,.T.);
#1533=ORIENTED_EDGE('',*,*,#1504,.F.);
#1534=ORIENTED_EDGE('',*,*,#1225,.T.);
#1535=ORIENTED_EDGE('',*,*,#1378,.F.);
#1536=EDGE_LOOP('',(#1516,#1517,#1518,#1519,#1520,#1521,#1522,#1523,#1524,#1525,#1526,#1527,
#1528,#1529,#1530,#1531,#1532,#1533,#1534,#1535));
#1537=FACE_BOUND('',#1536,.T.);
#1538=ADVANCED_FACE('F1200',(#1537),#1515,.F.);
#1539=CARTESIAN_POINT('',(-14.075,48.35,-23.58125));
#1540=DIRECTION('',(1.,0.,0.));
#1541=DIRECTION('',(0.,1.,0.));
#1542=AXIS2_PLACEMENT_3D('',#1539,#1540,#1541);
#1543=PLANE('',#1542);
#1544=ORIENTED_EDGE('',*,*,#326,.T.);
#1545=DIRECTION('',(0.,0.,-1.));
#1546=VECTOR('',#1545,1.);
#1547=CARTESIAN_POINT('',(-14.075,42.9262098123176,-23.58125));
#1548=LINE('',#1547,#1546);
#1549=CARTESIAN_POINT('',(-14.075,42.9262098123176,-23.58125));
#1550=VERTEX_POINT('',#1549);
#1551=EDGE_CURVE('E379',#1550,#317,#1548,.T.);
#1552=ORIENTED_EDGE('',*,*,#1551,.F.);
#1553=DIRECTION('',(0.,-1.,0.));
#1554=VECTOR('',#1553,1.);
#1555=CARTESIAN_POINT('',(-14.075,48.35,-23.58125));
#1556=LINE('',#1555,#1554);
#1557=CARTESIAN_POINT('',(-14.075,25.0737901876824,-23.58125));
#1558=VERTEX_POINT('',#1557);
#1559=EDGE_CURVE('E390',#1550,#1558,#1556,.T.);
#1560=ORIENTED_EDGE('',*,*,#1559,.T.);
#1561=DIRECTION('',(0.,0.,1.));
#1562=VECTOR('',#1561,1.);
#1563=CARTESIAN_POINT('',(-14.075,25.0737901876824,-23.58125));
#1564=LINE('',#1563,#1562);
#1565=EDGE_CURVE('E404',#325,#1558,#1564,.T.);
#1566=ORIENTED_EDGE('',*,*,#1565,.F.);
#1567=EDGE_LOOP('',(#1544,#1552,#1560,#1566));
#1568=FACE_BOUND('',#1567,.T.);
#1569=ADVANCED_FACE('F400',(#1568),#1543,.T.);
#1570=CARTESIAN_POINT('',(-16.125,19.65,-23.58125));
#1571=DIRECTION('',(1.,0.,0.));
#1572=DIRECTION('',(0.,1.,0.));
#1573=AXIS2_PLACEMENT_3D('',#1570,#1571,#1572);
#1574=PLANE('',#1573);
#1575=ORIENTED_EDGE('',*,*,#180,.T.);
#1576=DIRECTION('',(0.,0.,1.));
#1577=VECTOR('',#1576,1.);
#1578=CARTESIAN_POINT('',(-16.125,18.9237901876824,-23.58125));
#1579=LINE('',#1578,#1577);
#1580=CARTESIAN_POINT('',(-16.125,18.9237901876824,-23.58125));
#1581=VERTEX_POINT('',#1580);
#1582=EDGE_CURVE('E445',#1581,#179,#1579,.F.);
#1583=ORIENTED_EDGE('',*,*,#1582,.F.);
#1584=DIRECTION('',(0.,-1.,0.));
#1585=VECTOR('',#1584,1.);
#1586=CARTESIAN_POINT('',(-16.125,19.65,-23.58125));
#1587=LINE('',#1586,#1585);
#1588=CARTESIAN_POINT('',(-16.125,14.525,-23.58125));
#1589=VERTEX_POINT('',#1588);
#1590=EDGE_CURVE('E398',#1581,#1589,#1587,.T.);
#1591=ORIENTED_EDGE('',*,*,#1590,.T.);
#1592=DIRECTION('',(0.,0.,-1.));
#1593=VECTOR('',#1592,1.);
#1594=CARTESIAN_POINT('',(-16.125,14.525,-23.58125));
#1595=LINE('',#1594,#1593);
#1596=EDGE_CURVE('E443',#177,#1589,#1595,.F.);
#1597=ORIENTED_EDGE('',*,*,#1596,.F.);
#1598=EDGE_LOOP('',(#1575,#1583,#1591,#1597));
#1599=FACE_BOUND('',#1598,.T.);
#1600=ADVANCED_FACE('F792',(#1599),#1574,.T.);
#1601=CARTESIAN_POINT('',(-16.125,12.475,-23.58125));
#1602=DIRECTION('',(0.,1.,0.));
#1603=DIRECTION('',(0.,0.,1.));
#1604=AXIS2_PLACEMENT_3D('',#1601,#1602,#1603);
#1605=PLANE('',#1604);
#1606=ORIENTED_EDGE('',*,*,#197,.T.);
#1607=DIRECTION('',(0.,0.,-1.));
#1608=VECTOR('',#1607,1.);
#1609=CARTESIAN_POINT('',(-14.075,12.475,-23.58125));
#1610=LINE('',#1609,#1608);
#1611=CARTESIAN_POINT('',(-14.075,12.475,-23.58125));
#1612=VERTEX_POINT('',#1611);
#1613=EDGE_CURVE('E452',#1612,#188,#1610,.T.);
#1614=ORIENTED_EDGE('',*,*,#1613,.F.);
#1615=DIRECTION('',(1.,0.,0.));
#1616=VECTOR('',#1615,1.);
#1617=CARTESIAN_POINT('',(-16.125,12.475,-23.58125));
#1618=LINE('',#1617,#1616);
#1619=CARTESIAN_POINT('',(-7.92500000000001,12.475,-23.58125));
#1620=VERTEX_POINT('',#1619);
#1621=EDGE_CURVE('E806',#1612,#1620,#1618,.T.);
#1622=ORIENTED_EDGE('',*,*,#1621,.T.);
#1623=DIRECTION('',(0.,0.,-1.));
#1624=VECTOR('',#1623,1.);
#1625=CARTESIAN_POINT('',(-7.92500000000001,12.475,-23.58125));
#1626=LINE('',#1625,#1624);
#1627=EDGE_CURVE('E450',#196,#1620,#1626,.F.);
#1628=ORIENTED_EDGE('',*,*,#1627,.F.);
#1629=EDGE_LOOP('',(#1606,#1614,#1622,#1628));
#1630=FACE_BOUND('',#1629,.T.);
#1631=ADVANCED_FACE('F881',(#1630),#1605,.T.);
#1632=CARTESIAN_POINT('',(-5.87499999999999,19.65,-23.58125));
#1633=DIRECTION('',(-1.,0.,0.));
#1634=DIRECTION('',(0.,-1.,0.));
#1635=AXIS2_PLACEMENT_3D('',#1632,#1633,#1634);
#1636=PLANE('',#1635);
#1637=ORIENTED_EDGE('',*,*,#214,.T.);
#1638=DIRECTION('',(0.,0.,-1.));
#1639=VECTOR('',#1638,1.);
#1640=CARTESIAN_POINT('',(-5.87500000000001,14.525,-23.58125));
#1641=LINE('',#1640,#1639);
#1642=CARTESIAN_POINT('',(-5.87500000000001,14.525,-23.58125));
#1643=VERTEX_POINT('',#1642);
#1644=EDGE_CURVE('E457',#1643,#205,#1641,.T.);
#1645=ORIENTED_EDGE('',*,*,#1644,.F.);
#1646=DIRECTION('',(0.,1.,0.));
#1647=VECTOR('',#1646,1.);
#1648=CARTESIAN_POINT('',(-5.87499999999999,19.65,-23.58125));
#1649=LINE('',#1648,#1647);
#1650=CARTESIAN_POINT('',(-5.87499999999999,18.9237901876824,-23.58125));
#1651=VERTEX_POINT('',#1650);
#1652=EDGE_CURVE('E809',#1643,#1651,#1649,.T.);
#1653=ORIENTED_EDGE('',*,*,#1652,.T.);
#1654=DIRECTION('',(0.,0.,-1.));
#1655=VECTOR('',#1654,1.);
#1656=CARTESIAN_POINT('',(-5.87499999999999,18.9237901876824,-23.58125));
#1657=LINE('',#1656,#1655);
#1658=EDGE_CURVE('E455',#213,#1651,#1657,.F.);
#1659=ORIENTED_EDGE('',*,*,#1658,.F.);
#1660=EDGE_LOOP('',(#1637,#1645,#1653,#1659));
#1661=FACE_BOUND('',#1660,.T.);
#1662=ADVANCED_FACE('F874',(#1661),#1636,.T.);
#1663=CARTESIAN_POINT('',(-7.92500000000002,48.35,-23.58125));
#1664=DIRECTION('',(-1.,0.,0.));
#1665=DIRECTION('',(0.,-1.,0.));
#1666=AXIS2_PLACEMENT_3D('',#1663,#1664,#1665);
#1667=PLANE('',#1666);
#1668=ORIENTED_EDGE('',*,*,#240,.T.);
#1669=DIRECTION('',(0.,0.,-1.));
#1670=VECTOR('',#1669,1.);
#1671=CARTESIAN_POINT('',(-7.92500000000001,25.0737901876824,-23.58125));
#1672=LINE('',#1671,#1670);
#1673=CARTESIAN_POINT('',(-7.92500000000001,25.0737901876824,-23.58125));
#1674=VERTEX_POINT('',#1673);
#1675=EDGE_CURVE('E403',#1674,#231,#1672,.T.);
#1676=ORIENTED_EDGE('',*,*,#1675,.F.);
#1677=DIRECTION('',(0.,1.,0.));
#1678=VECTOR('',#1677,1.);
#1679=CARTESIAN_POINT('',(-7.92500000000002,48.35,-23.58125));
#1680=LINE('',#1679,#1678);
#1681=CARTESIAN_POINT('',(-7.92500000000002,42.9262098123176,-23.58125));
#1682=VERTEX_POINT('',#1681);
#1683=EDGE_CURVE('E814',#1674,#1682,#1680,.T.);
#1684=ORIENTED_EDGE('',*,*,#1683,.T.);
#1685=DIRECTION('',(0.,0.,1.));
#1686=VECTOR('',#1685,1.);
#1687=CARTESIAN_POINT('',(-7.92500000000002,42.9262098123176,-23.58125));
#1688=LINE('',#1687,#1686);
#1689=EDGE_CURVE('E386',#239,#1682,#1688,.T.);
#1690=ORIENTED_EDGE('',*,*,#1689,.F.);
#1691=EDGE_LOOP('',(#1668,#1676,#1684,#1690));
#1692=FACE_BOUND('',#1691,.T.);
#1693=ADVANCED_FACE('F859',(#1692),#1667,.T.);
#1694=CARTESIAN_POINT('',(-5.87500000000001,55.525,-23.58125));
#1695=DIRECTION('',(-1.,0.,0.));
#1696=DIRECTION('',(0.,0.,1.));
#1697=AXIS2_PLACEMENT_3D('',#1694,#1695,#1696);
#1698=PLANE('',#1697);
#1699=ORIENTED_EDGE('',*,*,#266,.T.);
#1700=DIRECTION('',(0.,0.,1.));
#1701=VECTOR('',#1700,1.);
#1702=CARTESIAN_POINT('',(-5.87500000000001,49.0762098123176,-23.58125));
#1703=LINE('',#1702,#1701);
#1704=CARTESIAN_POINT('',(-5.87500000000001,49.0762098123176,-23.58125));
#1705=VERTEX_POINT('',#1704);
#1706=EDGE_CURVE('E465',#1705,#257,#1703,.F.);
#1707=ORIENTED_EDGE('',*,*,#1706,.F.);
#1708=DIRECTION('',(0.,1.,0.));
#1709=VECTOR('',#1708,1.);
#1710=CARTESIAN_POINT('',(-5.87500000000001,55.525,-23.58125));
#1711=LINE('',#1710,#1709);
#1712=CARTESIAN_POINT('',(-5.87500000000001,53.475,-23.58125));
#1713=VERTEX_POINT('',#1712);
#1714=EDGE_CURVE('E817',#1705,#1713,#1711,.T.);
#1715=ORIENTED_EDGE('',*,*,#1714,.T.);
#1716=DIRECTION('',(0.,0.,-1.));
#1717=VECTOR('',#1716,1.);
#1718=CARTESIAN_POINT('',(-5.87500000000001,53.475,-23.58125));
#1719=LINE('',#1718,#1717);
#1720=EDGE_CURVE('E463',#265,#1713,#1719,.F.);
#1721=ORIENTED_EDGE('',*,*,#1720,.F.);
#1722=EDGE_LOOP('',(#1699,#1707,#1715,#1721));
#1723=FACE_BOUND('',#1722,.T.);
#1724=ADVANCED_FACE('F844',(#1723),#1698,.T.);
#1725=CARTESIAN_POINT('',(-16.125,55.525,-23.58125));
#1726=DIRECTION('',(0.,-1.,0.));
#1727=DIRECTION('',(0.,0.,-1.));
#1728=AXIS2_PLACEMENT_3D('',#1725,#1726,#1727);
#1729=PLANE('',#1728);
#1730=ORIENTED_EDGE('',*,*,#283,.T.);
#1731=DIRECTION('',(0.,0.,-1.));
#1732=VECTOR('',#1731,1.);
#1733=CARTESIAN_POINT('',(-7.92500000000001,55.525,-23.58125));
#1734=LINE('',#1733,#1732);
#1735=CARTESIAN_POINT('',(-7.92500000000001,55.525,-23.58125));
#1736=VERTEX_POINT('',#1735);
#1737=EDGE_CURVE('E48',#1736,#274,#1734,.T.);
#1738=ORIENTED_EDGE('',*,*,#1737,.F.);
#1739=DIRECTION('',(-1.,0.,0.));
#1740=VECTOR('',#1739,1.);
#1741=CARTESIAN_POINT('',(-16.125,55.525,-23.58125));
#1742=LINE('',#1741,#1740);
#1743=CARTESIAN_POINT('',(-14.075,55.525,-23.58125));
#1744=VERTEX_POINT('',#1743);
#1745=EDGE_CURVE('E820',#1736,#1744,#1742,.T.);
#1746=ORIENTED_EDGE('',*,*,#1745,.T.);
#1747=DIRECTION('',(0.,0.,-1.));
#1748=VECTOR('',#1747,1.);
#1749=CARTESIAN_POINT('',(-14.075,55.525,-23.58125));
#1750=LINE('',#1749,#1748);
#1751=EDGE_CURVE('E424',#282,#1744,#1750,.F.);
#1752=ORIENTED_EDGE('',*,*,#1751,.F.);
#1753=EDGE_LOOP('',(#1730,#1738,#1746,#1752));
#1754=FACE_BOUND('',#1753,.T.);
#1755=ADVANCED_FACE('F839',(#1754),#1729,.T.);
#1756=CARTESIAN_POINT('',(-16.125,55.525,-23.58125));
#1757=DIRECTION('',(1.,0.,0.));
#1758=DIRECTION('',(0.,0.,-1.));
#1759=AXIS2_PLACEMENT_3D('',#1756,#1757,#1758);
#1760=PLANE('',#1759);
#1761=ORIENTED_EDGE('',*,*,#300,.T.);
#1762=DIRECTION('',(0.,0.,-1.));
#1763=VECTOR('',#1762,1.);
#1764=CARTESIAN_POINT('',(-16.125,53.475,-23.58125));
#1765=LINE('',#1764,#1763);
#1766=CARTESIAN_POINT('',(-16.125,53.475,-23.58125));
#1767=VERTEX_POINT('',#1766);
#1768=EDGE_CURVE('E420',#1767,#291,#1765,.T.);
#1769=ORIENTED_EDGE('',*,*,#1768,.F.);
#1770=DIRECTION('',(0.,-1.,0.));
#1771=VECTOR('',#1770,1.);
#1772=CARTESIAN_POINT('',(-16.125,55.525,-23.58125));
#1773=LINE('',#1772,#1771);
#1774=CARTESIAN_POINT('',(-16.125,49.0762098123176,-23.58125));
#1775=VERTEX_POINT('',#1774);
#1776=EDGE_CURVE('E408',#1767,#1775,#1773,.T.);
#1777=ORIENTED_EDGE('',*,*,#1776,.T.);
#1778=DIRECTION('',(0.,0.,-1.));
#1779=VECTOR('',#1778,1.);
#1780=CARTESIAN_POINT('',(-16.125,49.0762098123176,-23.58125));
#1781=LINE('',#1780,#1779);
#1782=EDGE_CURVE('E418',#299,#1775,#1781,.F.);
#1783=ORIENTED_EDGE('',*,*,#1782,.F.);
#1784=EDGE_LOOP('',(#1761,#1769,#1777,#1783));
#1785=FACE_BOUND('',#1784,.T.);
#1786=ADVANCED_FACE('F827',(#1785),#1760,.T.);
#1787=CARTESIAN_POINT('',(-22.275,42.9262098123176,-23.58125));
#1788=DIRECTION('',(0.,0.,-1.));
#1789=DIRECTION('',(-1.,0.,0.));
#1790=AXIS2_PLACEMENT_3D('',#1787,#1788,#1789);
#1791=CYLINDRICAL_SURFACE('',#1790,8.2);
#1792=ORIENTED_EDGE('',*,*,#318,.T.);
#1793=DIRECTION('',(0.,0.,-1.));
#1794=VECTOR('',#1793,1.);
#1795=CARTESIAN_POINT('',(-15.715,47.8462098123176,-23.58125));
#1796=LINE('',#1795,#1794);
#1797=CARTESIAN_POINT('',(-15.715,47.8462098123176,-23.58125));
#1798=VERTEX_POINT('',#1797);
#1799=EDGE_CURVE('E382',#1798,#308,#1796,.T.);
#1800=ORIENTED_EDGE('',*,*,#1799,.F.);
#1801=CARTESIAN_POINT('',(-22.275,42.9262098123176,-23.58125));
#1802=DIRECTION('',(0.,0.,-1.));
#1803=DIRECTION('',(-1.,0.,0.));
#1804=AXIS2_PLACEMENT_3D('',#1801,#1802,#1803);
#1805=CIRCLE('',#1804,8.2);
#1806=EDGE_CURVE('E375',#1798,#1550,#1805,.T.);
#1807=ORIENTED_EDGE('',*,*,#1806,.T.);
#1808=ORIENTED_EDGE('',*,*,#1551,.T.);
#1809=EDGE_LOOP('',(#1792,#1800,#1807,#1808));
#1810=FACE_BOUND('',#1809,.T.);
#1811=ADVANCED_FACE('F377',(#1810),#1791,.T.);
#1812=CARTESIAN_POINT('',(0.274999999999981,42.9262098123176,-23.58125));
#1813=DIRECTION('',(0.,0.,1.));
#1814=DIRECTION('',(1.,0.,0.));
#1815=AXIS2_PLACEMENT_3D('',#1812,#1813,#1814);
#1816=CYLINDRICAL_SURFACE('',#1815,8.2);
#1817=ORIENTED_EDGE('',*,*,#249,.T.);
#1818=ORIENTED_EDGE('',*,*,#1689,.T.);
#1819=CARTESIAN_POINT('',(0.274999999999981,42.9262098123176,-23.58125));
#1820=DIRECTION('',(0.,0.,-1.));
#1821=DIRECTION('',(-1.,0.,0.));
#1822=AXIS2_PLACEMENT_3D('',#1819,#1820,#1821);
#1823=CIRCLE('',#1822,8.2);
#1824=CARTESIAN_POINT('',(-6.28500000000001,47.8462098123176,-23.58125));
#1825=VERTEX_POINT('',#1824);
#1826=EDGE_CURVE('E385',#1682,#1825,#1823,.T.);
#1827=ORIENTED_EDGE('',*,*,#1826,.T.);
#1828=DIRECTION('',(0.,0.,1.));
#1829=VECTOR('',#1828,1.);
#1830=CARTESIAN_POINT('',(-6.28500000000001,47.8462098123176,-23.58125));
#1831=LINE('',#1830,#1829);
#1832=EDGE_CURVE('E468',#248,#1825,#1831,.T.);
#1833=ORIENTED_EDGE('',*,*,#1832,.F.);
#1834=EDGE_LOOP('',(#1817,#1818,#1827,#1833));
#1835=FACE_BOUND('',#1834,.T.);
#1836=ADVANCED_FACE('F854',(#1835),#1816,.T.);
#1837=CARTESIAN_POINT('',(0.274999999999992,25.0737901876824,-23.58125));
#1838=DIRECTION('',(0.,0.,-1.));
#1839=DIRECTION('',(-1.,0.,0.));
#1840=AXIS2_PLACEMENT_3D('',#1837,#1838,#1839);
#1841=CYLINDRICAL_SURFACE('',#1840,8.2);
#1842=ORIENTED_EDGE('',*,*,#232,.T.);
#1843=DIRECTION('',(0.,0.,-1.));
#1844=VECTOR('',#1843,1.);
#1845=CARTESIAN_POINT('',(-6.285,20.1537901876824,-23.58125));
#1846=LINE('',#1845,#1844);
#1847=CARTESIAN_POINT('',(-6.285,20.1537901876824,-23.58125));
#1848=VERTEX_POINT('',#1847);
#1849=EDGE_CURVE('E460',#1848,#222,#1846,.T.);
#1850=ORIENTED_EDGE('',*,*,#1849,.F.);
#1851=CARTESIAN_POINT('',(0.274999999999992,25.0737901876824,-23.58125));
#1852=DIRECTION('',(0.,0.,-1.));
#1853=DIRECTION('',(-1.,0.,0.));
#1854=AXIS2_PLACEMENT_3D('',#1851,#1852,#1853);
#1855=CIRCLE('',#1854,8.2);
#1856=EDGE_CURVE('E415',#1848,#1674,#1855,.T.);
#1857=ORIENTED_EDGE('',*,*,#1856,.T.);
#1858=ORIENTED_EDGE('',*,*,#1675,.T.);
#1859=EDGE_LOOP('',(#1842,#1850,#1857,#1858));
#1860=FACE_BOUND('',#1859,.T.);
#1861=ADVANCED_FACE('F865',(#1860),#1841,.T.);
#1862=CARTESIAN_POINT('',(-22.275,25.0737901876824,-23.58125));
#1863=DIRECTION('',(0.,0.,1.));
#1864=DIRECTION('',(1.,0.,0.));
#1865=AXIS2_PLACEMENT_3D('',#1862,#1863,#1864);
#1866=CYLINDRICAL_SURFACE('',#1865,8.2);
#1867=ORIENTED_EDGE('',*,*,#335,.T.);
#1868=ORIENTED_EDGE('',*,*,#1565,.T.);
#1869=CARTESIAN_POINT('',(-22.275,25.0737901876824,-23.58125));
#1870=DIRECTION('',(0.,0.,-1.));
#1871=DIRECTION('',(-1.,0.,0.));
#1872=AXIS2_PLACEMENT_3D('',#1869,#1870,#1871);
#1873=CIRCLE('',#1872,8.2);
#1874=CARTESIAN_POINT('',(-15.715,20.1537901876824,-23.58125));
#1875=VERTEX_POINT('',#1874);
#1876=EDGE_CURVE('E395',#1558,#1875,#1873,.T.);
#1877=ORIENTED_EDGE('',*,*,#1876,.T.);
#1878=DIRECTION('',(0.,0.,1.));
#1879=VECTOR('',#1878,1.);
#1880=CARTESIAN_POINT('',(-15.715,20.1537901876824,-23.58125));
#1881=LINE('',#1880,#1879);
#1882=EDGE_CURVE('E448',#334,#1875,#1881,.T.);
#1883=ORIENTED_EDGE('',*,*,#1882,.F.);
#1884=EDGE_LOOP('',(#1867,#1868,#1877,#1883));
#1885=FACE_BOUND('',#1884,.T.);
#1886=ADVANCED_FACE('F803',(#1885),#1866,.T.);
#1887=CARTESIAN_POINT('',(-14.075,53.475,-23.58125));
#1888=DIRECTION('',(0.,0.,-1.));
#1889=DIRECTION('',(-1.,0.,0.));
#1890=AXIS2_PLACEMENT_3D('',#1887,#1888,#1889);
#1891=CYLINDRICAL_SURFACE('',#1890,2.05);
#1892=ORIENTED_EDGE('',*,*,#1751,.T.);
#1893=CARTESIAN_POINT('',(-14.075,53.475,-23.58125));
#1894=DIRECTION('',(0.,0.,-1.));
#1895=DIRECTION('',(-1.,0.,0.));
#1896=AXIS2_PLACEMENT_3D('',#1893,#1894,#1895);
#1897=CIRCLE('',#1896,2.05);
#1898=EDGE_CURVE('E440',#1744,#1767,#1897,.F.);
#1899=ORIENTED_EDGE('',*,*,#1898,.T.);
#1900=ORIENTED_EDGE('',*,*,#1768,.T.);
#1901=ORIENTED_EDGE('',*,*,#292,.F.);
#1902=EDGE_LOOP('',(#1892,#1899,#1900,#1901));
#1903=FACE_BOUND('',#1902,.T.);
#1904=ADVANCED_FACE('F834',(#1903),#1891,.F.);
#1905=CARTESIAN_POINT('',(-14.075,49.0762098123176,-23.58125));
#1906=DIRECTION('',(0.,0.,-1.));
#1907=DIRECTION('',(-1.,0.,0.));
#1908=AXIS2_PLACEMENT_3D('',#1905,#1906,#1907);
#1909=CYLINDRICAL_SURFACE('',#1908,2.05);
#1910=ORIENTED_EDGE('',*,*,#1782,.T.);
#1911=CARTESIAN_POINT('',(-14.075,49.0762098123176,-23.58125));
#1912=DIRECTION('',(0.,0.,-1.));
#1913=DIRECTION('',(-1.,0.,0.));
#1914=AXIS2_PLACEMENT_3D('',#1911,#1912,#1913);
#1915=CIRCLE('',#1914,2.05);
#1916=EDGE_CURVE('E438',#1775,#1798,#1915,.F.);
#1917=ORIENTED_EDGE('',*,*,#1916,.T.);
#1918=ORIENTED_EDGE('',*,*,#1799,.T.);
#1919=ORIENTED_EDGE('',*,*,#309,.F.);
#1920=EDGE_LOOP('',(#1910,#1917,#1918,#1919));
#1921=FACE_BOUND('',#1920,.T.);
#1922=ADVANCED_FACE('F831',(#1921),#1909,.F.);
#1923=CARTESIAN_POINT('',(-14.075,18.9237901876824,-23.58125));
#1924=DIRECTION('',(0.,0.,1.));
#1925=DIRECTION('',(1.,0.,0.));
#1926=AXIS2_PLACEMENT_3D('',#1923,#1924,#1925);
#1927=CYLINDRICAL_SURFACE('',#1926,2.05);
#1928=ORIENTED_EDGE('',*,*,#1882,.T.);
#1929=CARTESIAN_POINT('',(-14.075,18.9237901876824,-23.58125));
#1930=DIRECTION('',(0.,0.,-1.));
#1931=DIRECTION('',(-1.,0.,0.));
#1932=AXIS2_PLACEMENT_3D('',#1929,#1930,#1931);
#1933=CIRCLE('',#1932,2.05);
#1934=EDGE_CURVE('E436',#1875,#1581,#1933,.F.);
#1935=ORIENTED_EDGE('',*,*,#1934,.T.);
#1936=ORIENTED_EDGE('',*,*,#1582,.T.);
#1937=ORIENTED_EDGE('',*,*,#342,.F.);
#1938=EDGE_LOOP('',(#1928,#1935,#1936,#1937));
#1939=FACE_BOUND('',#1938,.T.);
#1940=ADVANCED_FACE('F796',(#1939),#1927,.F.);
#1941=CARTESIAN_POINT('',(-14.075,14.525,-23.58125));
#1942=DIRECTION('',(0.,0.,-1.));
#1943=DIRECTION('',(-1.,0.,0.));
#1944=AXIS2_PLACEMENT_3D('',#1941,#1942,#1943);
#1945=CYLINDRICAL_SURFACE('',#1944,2.05);
#1946=ORIENTED_EDGE('',*,*,#1596,.T.);
#1947=CARTESIAN_POINT('',(-14.075,14.525,-23.58125));
#1948=DIRECTION('',(0.,0.,-1.));
#1949=DIRECTION('',(-1.,0.,0.));
#1950=AXIS2_PLACEMENT_3D('',#1947,#1948,#1949);
#1951=CIRCLE('',#1950,2.05);
#1952=EDGE_CURVE('E434',#1589,#1612,#1951,.F.);
#1953=ORIENTED_EDGE('',*,*,#1952,.T.);
#1954=ORIENTED_EDGE('',*,*,#1613,.T.);
#1955=ORIENTED_EDGE('',*,*,#189,.F.);
#1956=EDGE_LOOP('',(#1946,#1953,#1954,#1955));
#1957=FACE_BOUND('',#1956,.T.);
#1958=ADVANCED_FACE('F883',(#1957),#1945,.F.);
#1959=CARTESIAN_POINT('',(-7.92500000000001,14.525,-23.58125));
#1960=DIRECTION('',(0.,0.,-1.));
#1961=DIRECTION('',(-1.,0.,0.));
#1962=AXIS2_PLACEMENT_3D('',#1959,#1960,#1961);
#1963=CYLINDRICAL_SURFACE('',#1962,2.05);
#1964=ORIENTED_EDGE('',*,*,#1627,.T.);
#1965=CARTESIAN_POINT('',(-7.92500000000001,14.525,-23.58125));
#1966=DIRECTION('',(0.,0.,-1.));
#1967=DIRECTION('',(-1.,0.,0.));
#1968=AXIS2_PLACEMENT_3D('',#1965,#1966,#1967);
#1969=CIRCLE('',#1968,2.05);
#1970=EDGE_CURVE('E432',#1620,#1643,#1969,.F.);
#1971=ORIENTED_EDGE('',*,*,#1970,.T.);
#1972=ORIENTED_EDGE('',*,*,#1644,.T.);
#1973=ORIENTED_EDGE('',*,*,#206,.F.);
#1974=EDGE_LOOP('',(#1964,#1971,#1972,#1973));
#1975=FACE_BOUND('',#1974,.T.);
#1976=ADVANCED_FACE('F876',(#1975),#1963,.F.);
#1977=CARTESIAN_POINT('',(-7.92499999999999,18.9237901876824,-23.58125));
#1978=DIRECTION('',(0.,0.,-1.));
#1979=DIRECTION('',(-1.,0.,0.));
#1980=AXIS2_PLACEMENT_3D('',#1977,#1978,#1979);
#1981=CYLINDRICAL_SURFACE('',#1980,2.05);
#1982=ORIENTED_EDGE('',*,*,#1658,.T.);
#1983=CARTESIAN_POINT('',(-7.92499999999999,18.9237901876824,-23.58125));
#1984=DIRECTION('',(0.,0.,-1.));
#1985=DIRECTION('',(-1.,0.,0.));
#1986=AXIS2_PLACEMENT_3D('',#1983,#1984,#1985);
#1987=CIRCLE('',#1986,2.05);
#1988=EDGE_CURVE('E430',#1651,#1848,#1987,.F.);
#1989=ORIENTED_EDGE('',*,*,#1988,.T.);
#1990=ORIENTED_EDGE('',*,*,#1849,.T.);
#1991=ORIENTED_EDGE('',*,*,#223,.F.);
#1992=EDGE_LOOP('',(#1982,#1989,#1990,#1991));
#1993=FACE_BOUND('',#1992,.T.);
#1994=ADVANCED_FACE('F868',(#1993),#1981,.F.);
#1995=CARTESIAN_POINT('',(-7.92500000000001,49.0762098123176,-23.58125));
#1996=DIRECTION('',(0.,0.,1.));
#1997=DIRECTION('',(1.,0.,0.));
#1998=AXIS2_PLACEMENT_3D('',#1995,#1996,#1997);
#1999=CYLINDRICAL_SURFACE('',#1998,2.05);
#2000=ORIENTED_EDGE('',*,*,#1832,.T.);
#2001=CARTESIAN_POINT('',(-7.92500000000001,49.0762098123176,-23.58125));
#2002=DIRECTION('',(0.,0.,-1.));
#2003=DIRECTION('',(-1.,0.,0.));
#2004=AXIS2_PLACEMENT_3D('',#2001,#2002,#2003);
#2005=CIRCLE('',#2004,2.05);
#2006=EDGE_CURVE('E428',#1825,#1705,#2005,.F.);
#2007=ORIENTED_EDGE('',*,*,#2006,.T.);
#2008=ORIENTED_EDGE('',*,*,#1706,.T.);
#2009=ORIENTED_EDGE('',*,*,#258,.F.);
#2010=EDGE_LOOP('',(#2000,#2007,#2008,#2009));
#2011=FACE_BOUND('',#2010,.T.);
#2012=ADVANCED_FACE('F850',(#2011),#1999,.F.);
#2013=CARTESIAN_POINT('',(-7.92500000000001,53.475,-23.58125));
#2014=DIRECTION('',(0.,0.,-1.));
#2015=DIRECTION('',(-1.,0.,0.));
#2016=AXIS2_PLACEMENT_3D('',#2013,#2014,#2015);
#2017=CYLINDRICAL_SURFACE('',#2016,2.05);
#2018=ORIENTED_EDGE('',*,*,#1720,.T.);
#2019=CARTESIAN_POINT('',(-7.92500000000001,53.475,-23.58125));
#2020=DIRECTION('',(0.,0.,-1.));
#2021=DIRECTION('',(-1.,0.,0.));
#2022=AXIS2_PLACEMENT_3D('',#2019,#2020,#2021);
#2023=CIRCLE('',#2022,2.05);
#2024=EDGE_CURVE('E426',#1713,#1736,#2023,.F.);
#2025=ORIENTED_EDGE('',*,*,#2024,.T.);
#2026=ORIENTED_EDGE('',*,*,#1737,.T.);
#2027=ORIENTED_EDGE('',*,*,#275,.F.);
#2028=EDGE_LOOP('',(#2018,#2025,#2026,#2027));
#2029=FACE_BOUND('',#2028,.T.);
#2030=ADVANCED_FACE('F842',(#2029),#2017,.F.);
#2031=CARTESIAN_POINT('',(-11.,39.125,-23.58125));
#2032=DIRECTION('',(0.,0.,-1.));
#2033=DIRECTION('',(-1.,0.,0.));
#2034=AXIS2_PLACEMENT_3D('',#2031,#2032,#2033);
#2035=PLANE('',#2034);
#2036=ORIENTED_EDGE('',*,*,#1745,.F.);
#2037=ORIENTED_EDGE('',*,*,#2024,.F.);
#2038=ORIENTED_EDGE('',*,*,#1714,.F.);
#2039=ORIENTED_EDGE('',*,*,#2006,.F.);
#2040=ORIENTED_EDGE('',*,*,#1826,.F.);
#2041=ORIENTED_EDGE('',*,*,#1683,.F.);
#2042=ORIENTED_EDGE('',*,*,#1856,.F.);
#2043=ORIENTED_EDGE('',*,*,#1988,.F.);
#2044=ORIENTED_EDGE('',*,*,#1652,.F.);
#2045=ORIENTED_EDGE('',*,*,#1970,.F.);
#2046=ORIENTED_EDGE('',*,*,#1621,.F.);
#2047=ORIENTED_EDGE('',*,*,#1952,.F.);
#2048=ORIENTED_EDGE('',*,*,#1590,.F.);
#2049=ORIENTED_EDGE('',*,*,#1934,.F.);
#2050=ORIENTED_EDGE('',*,*,#1876,.F.);
#2051=ORIENTED_EDGE('',*,*,#1559,.F.);
#2052=ORIENTED_EDGE('',*,*,#1806,.F.);
#2053=ORIENTED_EDGE('',*,*,#1916,.F.);
#2054=ORIENTED_EDGE('',*,*,#1776,.F.);
#2055=ORIENTED_EDGE('',*,*,#1898,.F.);
#2056=EDGE_LOOP('',(#2036,#2037,#2038,#2039,#2040,#2041,#2042,#2043,#2044,#2045,#2046,#2047,
#2048,#2049,#2050,#2051,#2052,#2053,#2054,#2055));
#2057=FACE_BOUND('',#2056,.T.);
#2058=ADVANCED_FACE('F392',(#2057),#2035,.T.);
#2059=CLOSED_SHELL('',(#46,#86,#126,#166,#570,#601,#641,#681,#754,#812,#870,#882,#894,#906,#918,
#930,#942,#954,#966,#986,#1006,#1018,#1049,#1080,#1111,#1142,#1173,#1204,#1235,#1266,#1291,
#1316,#1341,#1366,#1384,#1402,#1420,#1438,#1456,#1474,#1492,#1510,#1538,#1569,#1600,#1631,#1662,
#1693,#1724,#1755,#1786,#1811,#1836,#1861,#1886,#1904,#1922,#1940,#1958,#1976,#1994,#2012,#2030,#2058));
#2060=MANIFOLD_SOLID_BREP('B2',#2059);
#2061=ADVANCED_BREP_SHAPE_REPRESENTATION('',(#18,#2060),#14);
#2062=SHAPE_DEFINITION_REPRESENTATION(#9,#2061);
ENDSEC;
END-ISO-10303-21;
